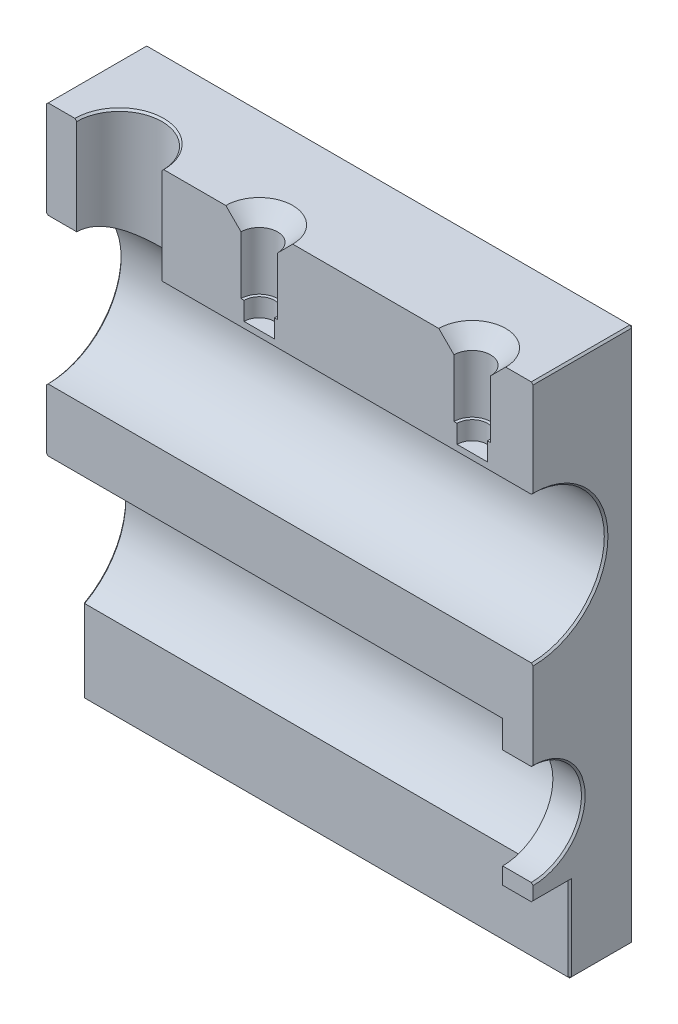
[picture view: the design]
ISO-10303-21;
HEADER;
FILE_DESCRIPTION(('STEP AP214'),'2;1');
FILE_NAME('part.step','',(''),(''),'','','');
FILE_SCHEMA(('AUTOMOTIVE_DESIGN { 1 0 10303 214 1 1 1 1 }'));
ENDSEC;
DATA;
#1=APPLICATION_CONTEXT('core data for automotive mechanical design processes');
#2=APPLICATION_PROTOCOL_DEFINITION('international standard','automotive_design',2000,#1);
#3=PRODUCT_CONTEXT('',#1,'mechanical');
#4=PRODUCT('Part','Part','',(#3));
#5=PRODUCT_RELATED_PRODUCT_CATEGORY('part','',(#4));
#6=PRODUCT_DEFINITION_FORMATION('','',#4);
#7=PRODUCT_DEFINITION_CONTEXT('part definition',#1,'design');
#8=PRODUCT_DEFINITION('design','',#6,#7);
#9=PRODUCT_DEFINITION_SHAPE('','',#8);
#10=(LENGTH_UNIT() NAMED_UNIT(*) SI_UNIT(.MILLI.,.METRE.));
#11=(NAMED_UNIT(*) PLANE_ANGLE_UNIT() SI_UNIT($,.RADIAN.));
#12=(NAMED_UNIT(*) SI_UNIT($,.STERADIAN.) SOLID_ANGLE_UNIT());
#13=UNCERTAINTY_MEASURE_WITH_UNIT(LENGTH_MEASURE(1.E-05),#10,'distance_accuracy_value','');
#14=(GEOMETRIC_REPRESENTATION_CONTEXT(3) GLOBAL_UNCERTAINTY_ASSIGNED_CONTEXT((#13)) GLOBAL_UNIT_ASSIGNED_CONTEXT((#10,
#11,#12)) REPRESENTATION_CONTEXT('',''));
#15=CARTESIAN_POINT('',(0.,0.,0.));
#16=DIRECTION('',(0.,0.,1.));
#17=DIRECTION('',(1.,0.,0.));
#18=AXIS2_PLACEMENT_3D('',#15,#16,#17);
#19=CARTESIAN_POINT('',(-40.,44.,35.));
#20=DIRECTION('',(1.,0.,0.));
#21=DIRECTION('',(0.,0.,-1.));
#22=AXIS2_PLACEMENT_3D('',#19,#20,#21);
#23=PLANE('',#22);
#24=DIRECTION('',(0.,-1.,0.));
#25=VECTOR('',#24,1.);
#26=CARTESIAN_POINT('',(-40.,63.9994038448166,16.5));
#27=LINE('',#26,#25);
#28=CARTESIAN_POINT('',(-40.,43.7,16.5));
#29=VERTEX_POINT('',#28);
#30=CARTESIAN_POINT('',(-40.,28.3,16.5));
#31=VERTEX_POINT('',#30);
#32=EDGE_CURVE('E275',#29,#31,#27,.T.);
#33=ORIENTED_EDGE('',*,*,#32,.F.);
#34=DIRECTION('',(0.,0.,-1.));
#35=VECTOR('',#34,1.);
#36=CARTESIAN_POINT('',(-40.,43.7,0.));
#37=LINE('',#36,#35);
#38=CARTESIAN_POINT('',(-40.,43.7,0.300000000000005));
#39=VERTEX_POINT('',#38);
#40=EDGE_CURVE('E287',#29,#39,#37,.T.);
#41=ORIENTED_EDGE('',*,*,#40,.T.);
#42=DIRECTION('',(0.,-1.,0.));
#43=VECTOR('',#42,1.);
#44=CARTESIAN_POINT('',(-40.,-44.,0.300000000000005));
#45=LINE('',#44,#43);
#46=CARTESIAN_POINT('',(-40.,-43.7,0.300000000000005));
#47=VERTEX_POINT('',#46);
#48=EDGE_CURVE('E299',#39,#47,#45,.T.);
#49=ORIENTED_EDGE('',*,*,#48,.T.);
#50=DIRECTION('',(0.,0.,1.));
#51=VECTOR('',#50,1.);
#52=CARTESIAN_POINT('',(-40.,-43.7,10.5));
#53=LINE('',#52,#51);
#54=CARTESIAN_POINT('',(-40.,-43.7,10.2));
#55=VERTEX_POINT('',#54);
#56=EDGE_CURVE('E302',#47,#55,#53,.T.);
#57=ORIENTED_EDGE('',*,*,#56,.T.);
#58=DIRECTION('',(0.,1.,0.));
#59=VECTOR('',#58,1.);
#60=CARTESIAN_POINT('',(-40.,-30.25,10.2));
#61=LINE('',#60,#59);
#62=CARTESIAN_POINT('',(-40.,-30.4285825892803,10.2));
#63=VERTEX_POINT('',#62);
#64=EDGE_CURVE('E310',#55,#63,#61,.T.);
#65=ORIENTED_EDGE('',*,*,#64,.T.);
#66=CARTESIAN_POINT('',(-40.,-19.,16.5));
#67=DIRECTION('',(1.,0.,0.));
#68=DIRECTION('',(0.,0.,-1.));
#69=AXIS2_PLACEMENT_3D('',#66,#67,#68);
#70=CIRCLE('',#69,13.05);
#71=CARTESIAN_POINT('',(-40.,-5.94999999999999,16.5));
#72=VERTEX_POINT('',#71);
#73=EDGE_CURVE('E312',#63,#72,#70,.T.);
#74=ORIENTED_EDGE('',*,*,#73,.T.);
#75=CARTESIAN_POINT('',(-40.,3.69999999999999,16.5));
#76=VERTEX_POINT('',#75);
#77=EDGE_CURVE('E293',#76,#72,#27,.T.);
#78=ORIENTED_EDGE('',*,*,#77,.F.);
#79=CARTESIAN_POINT('',(-40.,16.,16.5));
#80=DIRECTION('',(1.,0.,0.));
#81=DIRECTION('',(0.,0.,-1.));
#82=AXIS2_PLACEMENT_3D('',#79,#80,#81);
#83=CIRCLE('',#82,12.3);
#84=EDGE_CURVE('E291',#76,#31,#83,.T.);
#85=ORIENTED_EDGE('',*,*,#84,.T.);
#86=EDGE_LOOP('',(#33,#41,#49,#57,#65,#74,#78,#85));
#87=FACE_BOUND('',#86,.T.);
#88=ADVANCED_FACE('F34',(#87),#23,.F.);
#89=CARTESIAN_POINT('',(35.,-19.,16.5));
#90=DIRECTION('',(-1.,0.,0.));
#91=DIRECTION('',(0.,0.,1.));
#92=AXIS2_PLACEMENT_3D('',#89,#90,#91);
#93=CYLINDRICAL_SURFACE('',#92,12.75);
#94=DIRECTION('',(-1.,0.,0.));
#95=VECTOR('',#94,1.);
#96=CARTESIAN_POINT('',(35.,-6.25,16.5));
#97=LINE('',#96,#95);
#98=CARTESIAN_POINT('',(-39.7,-6.25,16.5));
#99=VERTEX_POINT('',#98);
#100=CARTESIAN_POINT('',(35.,-6.25,16.5));
#101=VERTEX_POINT('',#100);
#102=EDGE_CURVE('E463',#99,#101,#97,.F.);
#103=ORIENTED_EDGE('',*,*,#102,.F.);
#104=CARTESIAN_POINT('',(-39.7,-19.,16.5));
#105=DIRECTION('',(1.,0.,0.));
#106=DIRECTION('',(0.,0.,-1.));
#107=AXIS2_PLACEMENT_3D('',#104,#105,#106);
#108=CIRCLE('',#107,12.75);
#109=CARTESIAN_POINT('',(-39.7,-30.25,10.5));
#110=VERTEX_POINT('',#109);
#111=EDGE_CURVE('E316',#99,#110,#108,.F.);
#112=ORIENTED_EDGE('',*,*,#111,.T.);
#113=DIRECTION('',(-1.,0.,0.));
#114=VECTOR('',#113,1.);
#115=CARTESIAN_POINT('',(35.,-30.25,10.5));
#116=LINE('',#115,#114);
#117=CARTESIAN_POINT('',(35.,-30.25,10.5));
#118=VERTEX_POINT('',#117);
#119=EDGE_CURVE('E733',#110,#118,#116,.F.);
#120=ORIENTED_EDGE('',*,*,#119,.T.);
#121=CARTESIAN_POINT('',(35.,-19.,16.5));
#122=DIRECTION('',(-1.,0.,0.));
#123=DIRECTION('',(0.,0.,1.));
#124=AXIS2_PLACEMENT_3D('',#121,#122,#123);
#125=CIRCLE('',#124,12.75);
#126=EDGE_CURVE('E723',#101,#118,#125,.T.);
#127=ORIENTED_EDGE('',*,*,#126,.F.);
#128=EDGE_LOOP('',(#103,#112,#120,#127));
#129=FACE_BOUND('',#128,.T.);
#130=ADVANCED_FACE('F645',(#129),#93,.F.);
#131=CARTESIAN_POINT('',(-105.,-30.,22.5));
#132=DIRECTION('',(0.,-1.,0.));
#133=DIRECTION('',(0.,0.,-1.));
#134=AXIS2_PLACEMENT_3D('',#131,#132,#133);
#135=PLANE('',#134);
#136=DIRECTION('',(0.,0.,1.));
#137=VECTOR('',#136,1.);
#138=CARTESIAN_POINT('',(39.7,-30.,22.5));
#139=LINE('',#138,#137);
#140=CARTESIAN_POINT('',(39.7,-30.,10.5));
#141=VERTEX_POINT('',#140);
#142=CARTESIAN_POINT('',(39.7,-30.,16.5));
#143=VERTEX_POINT('',#142);
#144=EDGE_CURVE('E368',#141,#143,#139,.T.);
#145=ORIENTED_EDGE('',*,*,#144,.T.);
#146=DIRECTION('',(-1.,0.,0.));
#147=VECTOR('',#146,1.);
#148=CARTESIAN_POINT('',(-105.,-30.,16.5));
#149=LINE('',#148,#147);
#150=CARTESIAN_POINT('',(35.,-30.,16.5));
#151=VERTEX_POINT('',#150);
#152=EDGE_CURVE('E473',#143,#151,#149,.T.);
#153=ORIENTED_EDGE('',*,*,#152,.T.);
#154=DIRECTION('',(0.,0.,-1.));
#155=VECTOR('',#154,1.);
#156=CARTESIAN_POINT('',(35.,-30.,22.5));
#157=LINE('',#156,#155);
#158=CARTESIAN_POINT('',(35.,-30.,10.5));
#159=VERTEX_POINT('',#158);
#160=EDGE_CURVE('E725',#151,#159,#157,.T.);
#161=ORIENTED_EDGE('',*,*,#160,.T.);
#162=DIRECTION('',(1.,0.,0.));
#163=VECTOR('',#162,1.);
#164=CARTESIAN_POINT('',(-105.,-30.,10.5));
#165=LINE('',#164,#163);
#166=EDGE_CURVE('E727',#159,#141,#165,.T.);
#167=ORIENTED_EDGE('',*,*,#166,.T.);
#168=EDGE_LOOP('',(#145,#153,#161,#167));
#169=FACE_BOUND('',#168,.T.);
#170=ADVANCED_FACE('F636',(#169),#135,.T.);
#171=CARTESIAN_POINT('',(40.,-44.,35.));
#172=DIRECTION('',(-1.,0.,0.));
#173=DIRECTION('',(0.,-1.,0.));
#174=AXIS2_PLACEMENT_3D('',#171,#172,#173);
#175=PLANE('',#174);
#176=DIRECTION('',(0.,-1.,0.));
#177=VECTOR('',#176,1.);
#178=CARTESIAN_POINT('',(40.,63.9994038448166,16.5));
#179=LINE('',#178,#177);
#180=CARTESIAN_POINT('',(40.,-27.55,16.5));
#181=VERTEX_POINT('',#180);
#182=CARTESIAN_POINT('',(40.,-29.7,16.5));
#183=VERTEX_POINT('',#182);
#184=EDGE_CURVE('E49',#181,#183,#179,.T.);
#185=ORIENTED_EDGE('',*,*,#184,.T.);
#186=DIRECTION('',(0.,0.,-1.));
#187=VECTOR('',#186,1.);
#188=CARTESIAN_POINT('',(40.,-29.7,10.5));
#189=LINE('',#188,#187);
#190=CARTESIAN_POINT('',(40.,-29.7,10.2));
#191=VERTEX_POINT('',#190);
#192=EDGE_CURVE('E360',#183,#191,#189,.T.);
#193=ORIENTED_EDGE('',*,*,#192,.T.);
#194=DIRECTION('',(0.,-1.,0.));
#195=VECTOR('',#194,1.);
#196=CARTESIAN_POINT('',(40.,-44.,10.2));
#197=LINE('',#196,#195);
#198=CARTESIAN_POINT('',(40.,-43.7,10.2));
#199=VERTEX_POINT('',#198);
#200=EDGE_CURVE('E358',#191,#199,#197,.T.);
#201=ORIENTED_EDGE('',*,*,#200,.T.);
#202=DIRECTION('',(0.,0.,-1.));
#203=VECTOR('',#202,1.);
#204=CARTESIAN_POINT('',(40.,-43.7,0.));
#205=LINE('',#204,#203);
#206=CARTESIAN_POINT('',(40.,-43.7,0.300000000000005));
#207=VERTEX_POINT('',#206);
#208=EDGE_CURVE('E356',#199,#207,#205,.T.);
#209=ORIENTED_EDGE('',*,*,#208,.T.);
#210=DIRECTION('',(0.,1.,0.));
#211=VECTOR('',#210,1.);
#212=CARTESIAN_POINT('',(40.,44.,0.300000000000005));
#213=LINE('',#212,#211);
#214=CARTESIAN_POINT('',(40.,43.7,0.300000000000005));
#215=VERTEX_POINT('',#214);
#216=EDGE_CURVE('E354',#207,#215,#213,.T.);
#217=ORIENTED_EDGE('',*,*,#216,.T.);
#218=DIRECTION('',(0.,0.,1.));
#219=VECTOR('',#218,1.);
#220=CARTESIAN_POINT('',(40.,43.7,35.));
#221=LINE('',#220,#219);
#222=CARTESIAN_POINT('',(40.,43.7,16.5));
#223=VERTEX_POINT('',#222);
#224=EDGE_CURVE('E351',#215,#223,#221,.T.);
#225=ORIENTED_EDGE('',*,*,#224,.T.);
#226=CARTESIAN_POINT('',(40.,28.3,16.5));
#227=VERTEX_POINT('',#226);
#228=EDGE_CURVE('E659',#223,#227,#179,.T.);
#229=ORIENTED_EDGE('',*,*,#228,.T.);
#230=CARTESIAN_POINT('',(40.,16.,16.5));
#231=DIRECTION('',(-1.,0.,0.));
#232=DIRECTION('',(0.,-1.,0.));
#233=AXIS2_PLACEMENT_3D('',#230,#231,#232);
#234=CIRCLE('',#233,12.3);
#235=CARTESIAN_POINT('',(40.,3.69999999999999,16.5));
#236=VERTEX_POINT('',#235);
#237=EDGE_CURVE('E362',#227,#236,#234,.T.);
#238=ORIENTED_EDGE('',*,*,#237,.T.);
#239=CARTESIAN_POINT('',(40.,-10.45,16.5));
#240=VERTEX_POINT('',#239);
#241=EDGE_CURVE('E57',#236,#240,#179,.T.);
#242=ORIENTED_EDGE('',*,*,#241,.T.);
#243=CARTESIAN_POINT('',(40.,-19.,16.5));
#244=DIRECTION('',(-1.,0.,0.));
#245=DIRECTION('',(0.,-1.,0.));
#246=AXIS2_PLACEMENT_3D('',#243,#244,#245);
#247=CIRCLE('',#246,8.55000000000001);
#248=EDGE_CURVE('E365',#240,#181,#247,.T.);
#249=ORIENTED_EDGE('',*,*,#248,.T.);
#250=EDGE_LOOP('',(#185,#193,#201,#209,#217,#225,#229,#238,#242,#249));
#251=FACE_BOUND('',#250,.T.);
#252=ADVANCED_FACE('F647',(#251),#175,.F.);
#253=CARTESIAN_POINT('',(-40.,44.,35.));
#254=DIRECTION('',(0.,1.,0.));
#255=DIRECTION('',(-1.,0.,0.));
#256=AXIS2_PLACEMENT_3D('',#253,#254,#255);
#257=PLANE('',#256);
#258=DIRECTION('',(0.,0.,1.));
#259=VECTOR('',#258,1.);
#260=CARTESIAN_POINT('',(-39.7,44.,35.));
#261=LINE('',#260,#259);
#262=CARTESIAN_POINT('',(-39.7,44.,0.300000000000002));
#263=VERTEX_POINT('',#262);
#264=CARTESIAN_POINT('',(-39.7,44.,16.5));
#265=VERTEX_POINT('',#264);
#266=EDGE_CURVE('E346',#263,#265,#261,.T.);
#267=ORIENTED_EDGE('',*,*,#266,.T.);
#268=DIRECTION('',(1.,0.,0.));
#269=VECTOR('',#268,1.);
#270=CARTESIAN_POINT('',(-40.,44.,16.5));
#271=LINE('',#270,#269);
#272=CARTESIAN_POINT('',(-35.3,44.,16.5));
#273=VERTEX_POINT('',#272);
#274=EDGE_CURVE('E278',#265,#273,#271,.T.);
#275=ORIENTED_EDGE('',*,*,#274,.T.);
#276=CARTESIAN_POINT('',(-28.,44.,16.5));
#277=DIRECTION('',(0.,1.,0.));
#278=DIRECTION('',(-1.,0.,0.));
#279=AXIS2_PLACEMENT_3D('',#276,#277,#278);
#280=CIRCLE('',#279,7.3);
#281=CARTESIAN_POINT('',(-20.7,44.,16.5));
#282=VERTEX_POINT('',#281);
#283=EDGE_CURVE('E348',#273,#282,#280,.F.);
#284=ORIENTED_EDGE('',*,*,#283,.T.);
#285=CARTESIAN_POINT('',(-10.5,44.,16.5));
#286=VERTEX_POINT('',#285);
#287=EDGE_CURVE('E393',#282,#286,#271,.T.);
#288=ORIENTED_EDGE('',*,*,#287,.T.);
#289=CARTESIAN_POINT('',(-5.,44.,16.5));
#290=DIRECTION('',(0.,1.,0.));
#291=DIRECTION('',(-1.,0.,0.));
#292=AXIS2_PLACEMENT_3D('',#289,#290,#291);
#293=CIRCLE('',#292,5.50000000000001);
#294=CARTESIAN_POINT('',(0.500000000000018,44.,16.5));
#295=VERTEX_POINT('',#294);
#296=EDGE_CURVE('E746',#286,#295,#293,.F.);
#297=ORIENTED_EDGE('',*,*,#296,.T.);
#298=CARTESIAN_POINT('',(24.5,44.,16.5));
#299=VERTEX_POINT('',#298);
#300=EDGE_CURVE('E422',#295,#299,#271,.T.);
#301=ORIENTED_EDGE('',*,*,#300,.T.);
#302=CARTESIAN_POINT('',(30.,44.,16.5));
#303=DIRECTION('',(0.,1.,0.));
#304=DIRECTION('',(-1.,0.,0.));
#305=AXIS2_PLACEMENT_3D('',#302,#303,#304);
#306=CIRCLE('',#305,5.50000000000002);
#307=CARTESIAN_POINT('',(35.5,44.,16.5));
#308=VERTEX_POINT('',#307);
#309=EDGE_CURVE('E752',#299,#308,#306,.F.);
#310=ORIENTED_EDGE('',*,*,#309,.T.);
#311=CARTESIAN_POINT('',(39.7,44.,16.5));
#312=VERTEX_POINT('',#311);
#313=EDGE_CURVE('E444',#308,#312,#271,.T.);
#314=ORIENTED_EDGE('',*,*,#313,.T.);
#315=DIRECTION('',(0.,0.,-1.));
#316=VECTOR('',#315,1.);
#317=CARTESIAN_POINT('',(39.7,44.,0.));
#318=LINE('',#317,#316);
#319=CARTESIAN_POINT('',(39.7,44.,0.300000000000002));
#320=VERTEX_POINT('',#319);
#321=EDGE_CURVE('E342',#312,#320,#318,.T.);
#322=ORIENTED_EDGE('',*,*,#321,.T.);
#323=DIRECTION('',(-1.,0.,0.));
#324=VECTOR('',#323,1.);
#325=CARTESIAN_POINT('',(-40.,44.,0.300000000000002));
#326=LINE('',#325,#324);
#327=EDGE_CURVE('E344',#320,#263,#326,.T.);
#328=ORIENTED_EDGE('',*,*,#327,.T.);
#329=EDGE_LOOP('',(#267,#275,#284,#288,#297,#301,#310,#314,#322,#328));
#330=FACE_BOUND('',#329,.T.);
#331=ADVANCED_FACE('F634',(#330),#257,.T.);
#332=CARTESIAN_POINT('',(105.,16.,16.5));
#333=DIRECTION('',(-1.,0.,0.));
#334=DIRECTION('',(0.,0.,1.));
#335=AXIS2_PLACEMENT_3D('',#332,#333,#334);
#336=CYLINDRICAL_SURFACE('',#335,12.);
#337=DIRECTION('',(-1.,0.,0.));
#338=VECTOR('',#337,1.);
#339=CARTESIAN_POINT('',(105.,28.,16.5));
#340=LINE('',#339,#338);
#341=CARTESIAN_POINT('',(-39.7,28.,16.5));
#342=VERTEX_POINT('',#341);
#343=CARTESIAN_POINT('',(-35.,28.,16.5));
#344=VERTEX_POINT('',#343);
#345=EDGE_CURVE('E395',#342,#344,#340,.F.);
#346=ORIENTED_EDGE('',*,*,#345,.F.);
#347=CARTESIAN_POINT('',(-39.7,16.,16.5));
#348=DIRECTION('',(1.,0.,0.));
#349=DIRECTION('',(0.,0.,-1.));
#350=AXIS2_PLACEMENT_3D('',#347,#348,#349);
#351=CIRCLE('',#350,12.);
#352=CARTESIAN_POINT('',(-39.7,4.,16.5));
#353=VERTEX_POINT('',#352);
#354=EDGE_CURVE('E300',#342,#353,#351,.F.);
#355=ORIENTED_EDGE('',*,*,#354,.T.);
#356=DIRECTION('',(-1.,0.,0.));
#357=VECTOR('',#356,1.);
#358=CARTESIAN_POINT('',(105.,4.,16.5));
#359=LINE('',#358,#357);
#360=CARTESIAN_POINT('',(39.7,4.,16.5));
#361=VERTEX_POINT('',#360);
#362=EDGE_CURVE('E450',#361,#353,#359,.T.);
#363=ORIENTED_EDGE('',*,*,#362,.F.);
#364=CARTESIAN_POINT('',(39.7,16.,16.5));
#365=DIRECTION('',(-1.,0.,0.));
#366=DIRECTION('',(0.,0.,1.));
#367=AXIS2_PLACEMENT_3D('',#364,#365,#366);
#368=CIRCLE('',#367,12.);
#369=CARTESIAN_POINT('',(39.7,28.,16.5));
#370=VERTEX_POINT('',#369);
#371=EDGE_CURVE('E305',#361,#370,#368,.F.);
#372=ORIENTED_EDGE('',*,*,#371,.T.);
#373=CARTESIAN_POINT('',(-21.,28.,16.5));
#374=VERTEX_POINT('',#373);
#375=EDGE_CURVE('E391',#374,#370,#340,.F.);
#376=ORIENTED_EDGE('',*,*,#375,.F.);
#377=CARTESIAN_POINT('',(-35.,28.,16.5));
#378=CARTESIAN_POINT('',(-34.9999987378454,27.9999988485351,16.6799242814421));
#379=CARTESIAN_POINT('',(-34.9930513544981,27.9959425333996,16.8599175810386));
#380=CARTESIAN_POINT('',(-34.965347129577,27.979813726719,17.2185590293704));
#381=CARTESIAN_POINT('',(-34.9445808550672,27.9677357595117,17.397206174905));
#382=CARTESIAN_POINT('',(-34.8894535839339,27.9358311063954,17.7520940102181));
#383=CARTESIAN_POINT('',(-34.8550630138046,27.9159875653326,17.9283285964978));
#384=CARTESIAN_POINT('',(-34.7731150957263,27.8690337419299,18.2767862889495));
#385=CARTESIAN_POINT('',(-34.7255520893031,27.8419203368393,18.449007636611));
#386=CARTESIAN_POINT('',(-34.6181125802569,27.7812332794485,18.7873368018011));
#387=CARTESIAN_POINT('',(-34.5583041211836,27.7476953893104,18.9534726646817));
#388=CARTESIAN_POINT('',(-34.4268387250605,27.6748137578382,19.2796970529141));
#389=CARTESIAN_POINT('',(-34.3551772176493,27.6354677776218,19.4397832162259));
#390=CARTESIAN_POINT('',(-34.1234941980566,27.5100054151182,19.9094672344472));
#391=CARTESIAN_POINT('',(-33.9466262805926,27.4163786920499,20.2089503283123));
#392=CARTESIAN_POINT('',(-33.538685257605,27.2090985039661,20.7965672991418));
#393=CARTESIAN_POINT('',(-33.3045675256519,27.0944753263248,21.0822174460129));
#394=CARTESIAN_POINT('',(-32.7952979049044,26.8601889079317,21.6127667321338));
#395=CARTESIAN_POINT('',(-32.5200951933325,26.7405195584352,21.8576145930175));
#396=CARTESIAN_POINT('',(-32.0633107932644,26.558790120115,22.2036501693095));
#397=CARTESIAN_POINT('',(-31.8941627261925,26.4946617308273,22.3204771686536));
#398=CARTESIAN_POINT('',(-31.5451446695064,26.370220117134,22.5394008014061));
#399=CARTESIAN_POINT('',(-31.3652730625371,26.3099074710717,22.6414952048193));
#400=CARTESIAN_POINT('',(-30.9959052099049,26.1953257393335,22.8298884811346));
#401=CARTESIAN_POINT('',(-30.806421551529,26.1410490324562,22.9162073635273));
#402=CARTESIAN_POINT('',(-30.4186545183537,26.0406610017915,23.0721943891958));
#403=CARTESIAN_POINT('',(-30.220374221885,25.9945468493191,23.141868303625));
#404=CARTESIAN_POINT('',(-29.8628196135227,25.922039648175,23.2495419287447));
#405=CARTESIAN_POINT('',(-29.7050462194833,25.8935497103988,23.2911410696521));
#406=CARTESIAN_POINT('',(-29.3859307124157,25.8435761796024,23.3633769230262));
#407=CARTESIAN_POINT('',(-29.2245893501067,25.8220911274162,23.3940159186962));
#408=CARTESIAN_POINT('',(-28.8994699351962,25.7868769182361,23.4439164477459));
#409=CARTESIAN_POINT('',(-28.7356943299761,25.7731404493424,23.4631887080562));
#410=CARTESIAN_POINT('',(-28.40670027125,25.7538937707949,23.4901239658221));
#411=CARTESIAN_POINT('',(-28.2414817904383,25.7483837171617,23.4977867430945));
#412=CARTESIAN_POINT('',(-27.9105866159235,25.7457981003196,23.5013873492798));
#413=CARTESIAN_POINT('',(-27.7449096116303,25.7487359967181,23.4973064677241));
#414=CARTESIAN_POINT('',(-27.414623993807,25.7629626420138,23.4774427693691));
#415=CARTESIAN_POINT('',(-27.2500153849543,25.7742514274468,23.461659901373));
#416=CARTESIAN_POINT('',(-26.9229899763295,25.8047656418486,23.4186171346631));
#417=CARTESIAN_POINT('',(-26.7605741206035,25.8239943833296,23.3913524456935));
#418=CARTESIAN_POINT('',(-26.4389929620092,25.8697209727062,23.3257017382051));
#419=CARTESIAN_POINT('',(-26.2798290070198,25.8962217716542,23.287311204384));
#420=CARTESIAN_POINT('',(-25.9669297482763,25.9553982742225,23.20020827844));
#421=CARTESIAN_POINT('',(-25.8131615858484,25.9880237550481,23.151579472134));
#422=CARTESIAN_POINT('',(-25.510410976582,26.0586461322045,23.0442920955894));
#423=CARTESIAN_POINT('',(-25.3614301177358,26.0966447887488,22.9856302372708));
#424=CARTESIAN_POINT('',(-24.9225783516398,26.2172134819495,22.7953246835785));
#425=CARTESIAN_POINT('',(-24.6406438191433,26.3063871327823,22.6493174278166));
#426=CARTESIAN_POINT('',(-24.0564857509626,26.5101947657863,22.295173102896));
#427=CARTESIAN_POINT('',(-23.7586926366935,26.6265962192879,22.0807404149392));
#428=CARTESIAN_POINT('',(-23.3402045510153,26.8026719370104,21.7268306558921));
#429=CARTESIAN_POINT('',(-23.2053174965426,26.8616545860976,21.6033783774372));
#430=CARTESIAN_POINT('',(-22.9453933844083,26.9788695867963,21.3460690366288));
#431=CARTESIAN_POINT('',(-22.8203580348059,27.0371018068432,21.212210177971));
#432=CARTESIAN_POINT('',(-22.5658626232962,27.1586667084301,20.9173138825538));
#433=CARTESIAN_POINT('',(-22.4377884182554,27.2217322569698,20.7549672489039));
#434=CARTESIAN_POINT('',(-22.195887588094,27.3435800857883,20.4185680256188));
#435=CARTESIAN_POINT('',(-22.0820552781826,27.4023640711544,20.2445201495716));
#436=CARTESIAN_POINT('',(-21.8696422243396,27.514040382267,19.8855855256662));
#437=CARTESIAN_POINT('',(-21.7710587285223,27.5669337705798,19.7007007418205));
#438=CARTESIAN_POINT('',(-21.5902466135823,27.6652982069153,19.3212090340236));
#439=CARTESIAN_POINT('',(-21.5080159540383,27.7107701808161,19.1266033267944));
#440=CARTESIAN_POINT('',(-21.3659479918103,27.7901405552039,18.7424190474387));
#441=CARTESIAN_POINT('',(-21.3049795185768,27.8246102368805,18.5533771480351));
#442=CARTESIAN_POINT('',(-21.19908556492,27.884887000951,18.1694901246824));
#443=CARTESIAN_POINT('',(-21.1541595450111,27.9106943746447,17.9746451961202));
#444=CARTESIAN_POINT('',(-21.0810785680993,27.9528483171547,17.5810015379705));
#445=CARTESIAN_POINT('',(-21.0529086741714,27.9692033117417,17.3822064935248));
#446=CARTESIAN_POINT('',(-21.0137528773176,27.991971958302,16.9823739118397));
#447=CARTESIAN_POINT('',(-21.0027648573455,27.9983868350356,16.781336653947));
#448=CARTESIAN_POINT('',(-20.9984475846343,28.0009058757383,16.4046741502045));
#449=CARTESIAN_POINT('',(-21.0030457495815,27.9982202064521,16.2290764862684));
#450=CARTESIAN_POINT('',(-21.0253944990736,27.9852007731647,15.8790052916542));
#451=CARTESIAN_POINT('',(-21.0431447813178,27.9748671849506,15.7045317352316));
#452=CARTESIAN_POINT('',(-21.0915660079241,27.946801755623,15.3580072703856));
#453=CARTESIAN_POINT('',(-21.1222362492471,27.9290703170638,15.1859562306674));
#454=CARTESIAN_POINT('',(-21.1961171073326,27.8866273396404,14.8454506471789));
#455=CARTESIAN_POINT('',(-21.2393280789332,27.8619156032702,14.6769962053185));
#456=CARTESIAN_POINT('',(-21.3370112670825,27.8065162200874,14.3474104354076));
#457=CARTESIAN_POINT('',(-21.3912916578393,27.7759308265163,14.1862049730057));
#458=CARTESIAN_POINT('',(-21.510979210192,27.7091816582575,13.8691523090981));
#459=CARTESIAN_POINT('',(-21.5763899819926,27.673016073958,13.7133068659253));
#460=CARTESIAN_POINT('',(-21.7884493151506,27.5572161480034,13.2550384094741));
#461=CARTESIAN_POINT('',(-21.9509951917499,27.4702377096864,12.9616490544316));
#462=CARTESIAN_POINT('',(-22.3326222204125,27.2734064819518,12.37495536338));
#463=CARTESIAN_POINT('',(-22.555831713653,27.1621140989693,12.0848514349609));
#464=CARTESIAN_POINT('',(-23.0432916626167,26.9326417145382,11.5438217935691));
#465=CARTESIAN_POINT('',(-23.3075898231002,26.8144538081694,11.2929423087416));
#466=CARTESIAN_POINT('',(-23.7481456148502,26.6328528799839,10.9355367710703));
#467=CARTESIAN_POINT('',(-23.912000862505,26.5682105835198,10.8140507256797));
#468=CARTESIAN_POINT('',(-24.2505815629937,26.4419087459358,10.5853076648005));
#469=CARTESIAN_POINT('',(-24.4253097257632,26.3802499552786,10.4780542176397));
#470=CARTESIAN_POINT('',(-24.7846784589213,26.2620430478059,10.2787542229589));
#471=CARTESIAN_POINT('',(-24.9693106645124,26.2054907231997,10.1866951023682));
#472=CARTESIAN_POINT('',(-25.3476313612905,26.0996108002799,10.0186633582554));
#473=CARTESIAN_POINT('',(-25.5413132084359,26.0502780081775,9.9426791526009));
#474=CARTESIAN_POINT('',(-25.894050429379,25.9705659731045,9.82228743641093));
#475=CARTESIAN_POINT('',(-26.0515884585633,25.9383925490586,9.77460351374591));
#476=CARTESIAN_POINT('',(-26.3707267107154,25.8807857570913,9.69025070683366));
#477=CARTESIAN_POINT('',(-26.5323247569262,25.8553488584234,9.65357605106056));
#478=CARTESIAN_POINT('',(-26.8585667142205,25.8120721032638,9.59169557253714));
#479=CARTESIAN_POINT('',(-27.0232078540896,25.7942256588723,9.56647980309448));
#480=CARTESIAN_POINT('',(-27.3545581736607,25.7667467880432,9.52782507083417));
#481=CARTESIAN_POINT('',(-27.5212673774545,25.7571144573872,9.5143862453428));
#482=CARTESIAN_POINT('',(-27.855951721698,25.7464199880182,9.49947260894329));
#483=CARTESIAN_POINT('',(-28.0239290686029,25.7453811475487,9.49803032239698));
#484=CARTESIAN_POINT('',(-28.3593803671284,25.7519757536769,9.50721802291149));
#485=CARTESIAN_POINT('',(-28.5268543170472,25.7596092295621,9.51784805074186));
#486=CARTESIAN_POINT('',(-28.8600682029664,25.7832553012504,9.55101969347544));
#487=CARTESIAN_POINT('',(-29.025807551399,25.7992706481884,9.57356521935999));
#488=CARTESIAN_POINT('',(-29.3543963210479,25.8390941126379,9.63025307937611));
#489=CARTESIAN_POINT('',(-29.517244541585,25.8629053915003,9.66440011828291));
#490=CARTESIAN_POINT('',(-29.8341783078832,25.9166803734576,9.74266092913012));
#491=CARTESIAN_POINT('',(-29.9883802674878,25.946438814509,9.78644614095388));
#492=CARTESIAN_POINT('',(-30.292360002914,26.011635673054,9.88406539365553));
#493=CARTESIAN_POINT('',(-30.442136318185,26.0470759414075,9.93790270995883));
#494=CARTESIAN_POINT('',(-30.883847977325,26.1604956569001,10.1137793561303));
#495=CARTESIAN_POINT('',(-31.1683244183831,26.2456025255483,10.2502230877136));
#496=CARTESIAN_POINT('',(-31.7559866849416,26.4412152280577,10.5819384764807));
#497=CARTESIAN_POINT('',(-32.0552420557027,26.5536132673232,10.7830494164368));
#498=CARTESIAN_POINT('',(-32.4775724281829,26.72530391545,11.1163603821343));
#499=CARTESIAN_POINT('',(-32.614008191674,26.7830904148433,11.2328288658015));
#500=CARTESIAN_POINT('',(-32.877635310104,26.8984984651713,11.4759756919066));
#501=CARTESIAN_POINT('',(-33.0048251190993,26.9561199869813,11.6026557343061));
#502=CARTESIAN_POINT('',(-33.2665773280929,27.0779780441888,11.8842517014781));
#503=CARTESIAN_POINT('',(-33.399663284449,27.1420060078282,12.0406336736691));
#504=CARTESIAN_POINT('',(-33.6521414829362,27.266527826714,12.3653212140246));
#505=CARTESIAN_POINT('',(-33.771538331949,27.3270228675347,12.5336227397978));
#506=CARTESIAN_POINT('',(-33.9957745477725,27.4429058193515,12.8815010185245));
#507=CARTESIAN_POINT('',(-34.100604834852,27.4982905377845,13.0610847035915));
#508=CARTESIAN_POINT('',(-34.2945268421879,27.6023434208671,13.4304046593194));
#509=CARTESIAN_POINT('',(-34.3836209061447,27.651012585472,13.6201394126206));
#510=CARTESIAN_POINT('',(-34.5411584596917,27.7380855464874,13.9993237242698));
#511=CARTESIAN_POINT('',(-34.610378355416,27.7768655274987,14.188363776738));
#512=CARTESIAN_POINT('',(-34.732595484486,27.8458978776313,14.5731165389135));
#513=CARTESIAN_POINT('',(-34.7855957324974,27.8761518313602,14.7688280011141));
#514=CARTESIAN_POINT('',(-34.8744337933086,27.9271337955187,15.1646440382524));
#515=CARTESIAN_POINT('',(-34.9103267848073,27.9478924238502,15.3647322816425));
#516=CARTESIAN_POINT('',(-34.9645814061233,27.9793530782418,15.767937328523));
#517=CARTESIAN_POINT('',(-34.9829587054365,27.9900640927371,15.9710512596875));
#518=CARTESIAN_POINT('',(-34.9949552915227,27.9970579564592,16.2287983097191));
#519=CARTESIAN_POINT('',(-34.9968464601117,27.9981606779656,16.2830132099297));
#520=CARTESIAN_POINT('',(-34.9993690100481,27.9996318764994,16.3914833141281));
#521=CARTESIAN_POINT('',(-35.00000038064,28.0000003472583,16.445738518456));
#522=CARTESIAN_POINT('',(-35.,28.,16.5));
#523=B_SPLINE_CURVE_WITH_KNOTS('',3,(#377,#378,#379,#380,#381,#382,#383,#384,#385,#386,#387,
#388,#389,#390,#391,#392,#393,#394,#395,#396,#397,#398,#399,#400,#401,#402,#403,#404,#405,#406,
#407,#408,#409,#410,#411,#412,#413,#414,#415,#416,#417,#418,#419,#420,#421,#422,#423,#424,#425,
#426,#427,#428,#429,#430,#431,#432,#433,#434,#435,#436,#437,#438,#439,#440,#441,#442,#443,#444,
#445,#446,#447,#448,#449,#450,#451,#452,#453,#454,#455,#456,#457,#458,#459,#460,#461,#462,#463,
#464,#465,#466,#467,#468,#469,#470,#471,#472,#473,#474,#475,#476,#477,#478,#479,#480,#481,#482,
#483,#484,#485,#486,#487,#488,#489,#490,#491,#492,#493,#494,#495,#496,#497,#498,#499,#500,#501,
#502,#503,#504,#505,#506,#507,#508,#509,#510,#511,#512,#513,#514,#515,#516,#517,#518,#519,#520,
#521,#522),.UNSPECIFIED.,.T.,.F.,(4,2,2,2,2,2,2,2,2,2,2,2,2,2,2,2,2,2,2,2,2,2,2,2,2,2,2,2,2,2,2,
2,2,2,2,2,2,2,2,2,2,2,2,2,2,2,2,2,2,2,2,2,2,2,2,2,2,2,2,2,2,2,2,2,2,2,2,2,2,2,2,2,4),(0.,
0.539714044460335,1.07979688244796,1.62105852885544,2.16255304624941,2.7011165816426,
3.23988826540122,4.3159766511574,5.47177129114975,6.62900769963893,7.27436377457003,
7.91981743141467,8.56444663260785,9.20885200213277,9.70525094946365,10.2015464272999,
10.6973727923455,11.1932085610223,11.6898347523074,12.1864631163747,12.6832988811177,
13.1803365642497,13.673463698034,14.1667527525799,15.1528453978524,16.3030243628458,
16.8789854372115,17.4550461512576,18.102797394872,18.7502892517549,19.3976641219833,
20.0449581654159,20.6488864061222,21.2527943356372,21.8561631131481,22.459457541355,
22.985843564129,23.5122174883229,24.0385627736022,24.5649229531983,25.0828370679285,
25.6009194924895,26.6363484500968,27.7797710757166,28.9245312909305,29.5658181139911,
30.2072654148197,30.8481792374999,31.4886296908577,31.9912636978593,32.4936337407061,
32.9955668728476,33.497505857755,34.0008052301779,34.5041063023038,35.0075726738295,
35.5112434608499,35.999853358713,36.4886227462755,37.4656692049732,38.594099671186,
39.1590902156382,39.7241750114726,40.3686847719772,41.0129769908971,41.6576690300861,
42.3022649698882,42.9164261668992,43.5304731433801,44.1425259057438,44.7540306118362,
44.9167959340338,45.0795626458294),.UNSPECIFIED.);
#524=EDGE_CURVE('E388',#374,#344,#523,.T.);
#525=ORIENTED_EDGE('',*,*,#524,.T.);
#526=EDGE_LOOP('',(#346,#355,#363,#372,#376,#525));
#527=FACE_BOUND('',#526,.T.);
#528=ADVANCED_FACE('F628',(#527),#336,.F.);
#529=CARTESIAN_POINT('',(35.,-19.,16.5));
#530=DIRECTION('',(-1.,0.,0.));
#531=DIRECTION('',(0.,0.,1.));
#532=AXIS2_PLACEMENT_3D('',#529,#530,#531);
#533=PLANE('',#532);
#534=ORIENTED_EDGE('',*,*,#160,.F.);
#535=DIRECTION('',(0.,1.,0.));
#536=VECTOR('',#535,1.);
#537=CARTESIAN_POINT('',(35.,-19.,16.5));
#538=LINE('',#537,#536);
#539=CARTESIAN_POINT('',(35.,-27.25,16.5));
#540=VERTEX_POINT('',#539);
#541=EDGE_CURVE('E464',#151,#540,#538,.T.);
#542=ORIENTED_EDGE('',*,*,#541,.T.);
#543=CARTESIAN_POINT('',(35.,-19.,16.5));
#544=DIRECTION('',(-1.,0.,0.));
#545=DIRECTION('',(0.,0.,1.));
#546=AXIS2_PLACEMENT_3D('',#543,#544,#545);
#547=CIRCLE('',#546,8.25);
#548=CARTESIAN_POINT('',(35.,-10.75,16.5));
#549=VERTEX_POINT('',#548);
#550=EDGE_CURVE('E720',#549,#540,#547,.T.);
#551=ORIENTED_EDGE('',*,*,#550,.F.);
#552=EDGE_CURVE('E460',#549,#101,#538,.T.);
#553=ORIENTED_EDGE('',*,*,#552,.T.);
#554=ORIENTED_EDGE('',*,*,#126,.T.);
#555=DIRECTION('',(0.,-1.,0.));
#556=VECTOR('',#555,1.);
#557=CARTESIAN_POINT('',(35.,-30.,10.5));
#558=LINE('',#557,#556);
#559=EDGE_CURVE('E730',#159,#118,#558,.T.);
#560=ORIENTED_EDGE('',*,*,#559,.F.);
#561=EDGE_LOOP('',(#534,#542,#551,#553,#554,#560));
#562=FACE_BOUND('',#561,.T.);
#563=ADVANCED_FACE('F633',(#562),#533,.T.);
#564=CARTESIAN_POINT('',(40.,-19.,16.5));
#565=DIRECTION('',(-1.,0.,0.));
#566=DIRECTION('',(0.,0.,1.));
#567=AXIS2_PLACEMENT_3D('',#564,#565,#566);
#568=CYLINDRICAL_SURFACE('',#567,8.25);
#569=DIRECTION('',(-1.,0.,0.));
#570=VECTOR('',#569,1.);
#571=CARTESIAN_POINT('',(40.,-10.75,16.5));
#572=LINE('',#571,#570);
#573=CARTESIAN_POINT('',(39.7,-10.75,16.5));
#574=VERTEX_POINT('',#573);
#575=EDGE_CURVE('E458',#549,#574,#572,.F.);
#576=ORIENTED_EDGE('',*,*,#575,.F.);
#577=ORIENTED_EDGE('',*,*,#550,.T.);
#578=DIRECTION('',(-1.,0.,0.));
#579=VECTOR('',#578,1.);
#580=CARTESIAN_POINT('',(40.,-27.25,16.5));
#581=LINE('',#580,#579);
#582=CARTESIAN_POINT('',(39.7,-27.25,16.5));
#583=VERTEX_POINT('',#582);
#584=EDGE_CURVE('E471',#583,#540,#581,.T.);
#585=ORIENTED_EDGE('',*,*,#584,.F.);
#586=CARTESIAN_POINT('',(39.7,-19.,16.5));
#587=DIRECTION('',(-1.,0.,0.));
#588=DIRECTION('',(0.,0.,1.));
#589=AXIS2_PLACEMENT_3D('',#586,#587,#588);
#590=CIRCLE('',#589,8.25);
#591=EDGE_CURVE('E371',#583,#574,#590,.F.);
#592=ORIENTED_EDGE('',*,*,#591,.T.);
#593=EDGE_LOOP('',(#576,#577,#585,#592));
#594=FACE_BOUND('',#593,.T.);
#595=ADVANCED_FACE('F613',(#594),#568,.F.);
#596=CARTESIAN_POINT('',(-28.,19.,16.5));
#597=DIRECTION('',(0.,1.,0.));
#598=DIRECTION('',(-1.,0.,0.));
#599=AXIS2_PLACEMENT_3D('',#596,#597,#598);
#600=CYLINDRICAL_SURFACE('',#599,7.);
#601=DIRECTION('',(0.,1.,0.));
#602=VECTOR('',#601,1.);
#603=CARTESIAN_POINT('',(-21.,19.,16.5));
#604=LINE('',#603,#602);
#605=CARTESIAN_POINT('',(-21.,43.7,16.5));
#606=VERTEX_POINT('',#605);
#607=EDGE_CURVE('E387',#606,#374,#604,.F.);
#608=ORIENTED_EDGE('',*,*,#607,.F.);
#609=CARTESIAN_POINT('',(-28.,43.7,16.5));
#610=DIRECTION('',(0.,1.,0.));
#611=DIRECTION('',(0.,0.,1.));
#612=AXIS2_PLACEMENT_3D('',#609,#610,#611);
#613=CIRCLE('',#612,7.);
#614=CARTESIAN_POINT('',(-35.,43.7,16.5));
#615=VERTEX_POINT('',#614);
#616=EDGE_CURVE('E374',#606,#615,#613,.T.);
#617=ORIENTED_EDGE('',*,*,#616,.T.);
#618=DIRECTION('',(0.,1.,0.));
#619=VECTOR('',#618,1.);
#620=CARTESIAN_POINT('',(-35.,19.,16.5));
#621=LINE('',#620,#619);
#622=EDGE_CURVE('E292',#344,#615,#621,.T.);
#623=ORIENTED_EDGE('',*,*,#622,.F.);
#624=ORIENTED_EDGE('',*,*,#524,.F.);
#625=EDGE_LOOP('',(#608,#617,#623,#624));
#626=FACE_BOUND('',#625,.T.);
#627=ADVANCED_FACE('F384',(#626),#600,.F.);
#628=CARTESIAN_POINT('',(30.,32.,16.5));
#629=DIRECTION('',(0.,1.,0.));
#630=DIRECTION('',(-1.,0.,0.));
#631=AXIS2_PLACEMENT_3D('',#628,#629,#630);
#632=PLANE('',#631);
#633=CARTESIAN_POINT('',(30.,32.,16.5));
#634=DIRECTION('',(0.,1.,0.));
#635=DIRECTION('',(-1.,0.,0.));
#636=AXIS2_PLACEMENT_3D('',#633,#634,#635);
#637=CIRCLE('',#636,3.);
#638=CARTESIAN_POINT('',(33.,32.,16.5));
#639=VERTEX_POINT('',#638);
#640=CARTESIAN_POINT('',(27.,32.,16.5));
#641=VERTEX_POINT('',#640);
#642=EDGE_CURVE('E706',#639,#641,#637,.T.);
#643=ORIENTED_EDGE('',*,*,#642,.T.);
#644=DIRECTION('',(1.,0.,0.));
#645=VECTOR('',#644,1.);
#646=CARTESIAN_POINT('',(30.,32.,16.5));
#647=LINE('',#646,#645);
#648=CARTESIAN_POINT('',(27.5,32.,16.5));
#649=VERTEX_POINT('',#648);
#650=EDGE_CURVE('E428',#641,#649,#647,.T.);
#651=ORIENTED_EDGE('',*,*,#650,.T.);
#652=CARTESIAN_POINT('',(30.,32.,16.5));
#653=DIRECTION('',(0.,1.,0.));
#654=DIRECTION('',(-1.,0.,0.));
#655=AXIS2_PLACEMENT_3D('',#652,#653,#654);
#656=CIRCLE('',#655,2.50000000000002);
#657=CARTESIAN_POINT('',(32.5,32.,16.5));
#658=VERTEX_POINT('',#657);
#659=EDGE_CURVE('E626',#649,#658,#656,.F.);
#660=ORIENTED_EDGE('',*,*,#659,.T.);
#661=EDGE_CURVE('E432',#658,#639,#647,.T.);
#662=ORIENTED_EDGE('',*,*,#661,.T.);
#663=EDGE_LOOP('',(#643,#651,#660,#662));
#664=FACE_BOUND('',#663,.T.);
#665=ADVANCED_FACE('F589',(#664),#632,.T.);
#666=CARTESIAN_POINT('',(30.,32.,16.5));
#667=DIRECTION('',(0.,1.,0.));
#668=DIRECTION('',(-1.,0.,0.));
#669=AXIS2_PLACEMENT_3D('',#666,#667,#668);
#670=CYLINDRICAL_SURFACE('',#669,3.);
#671=DIRECTION('',(0.,1.,0.));
#672=VECTOR('',#671,1.);
#673=CARTESIAN_POINT('',(33.,32.,16.5));
#674=LINE('',#673,#672);
#675=CARTESIAN_POINT('',(33.,41.4999999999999,16.5));
#676=VERTEX_POINT('',#675);
#677=EDGE_CURVE('E439',#676,#639,#674,.F.);
#678=ORIENTED_EDGE('',*,*,#677,.F.);
#679=CARTESIAN_POINT('',(30.,41.4999999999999,16.5));
#680=DIRECTION('',(0.,1.,0.));
#681=DIRECTION('',(0.,0.,1.));
#682=AXIS2_PLACEMENT_3D('',#679,#680,#681);
#683=CIRCLE('',#682,3.);
#684=CARTESIAN_POINT('',(27.,41.4999999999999,16.5));
#685=VERTEX_POINT('',#684);
#686=EDGE_CURVE('E742',#676,#685,#683,.T.);
#687=ORIENTED_EDGE('',*,*,#686,.T.);
#688=DIRECTION('',(0.,1.,0.));
#689=VECTOR('',#688,1.);
#690=CARTESIAN_POINT('',(27.,32.,16.5));
#691=LINE('',#690,#689);
#692=EDGE_CURVE('E426',#641,#685,#691,.T.);
#693=ORIENTED_EDGE('',*,*,#692,.F.);
#694=ORIENTED_EDGE('',*,*,#642,.F.);
#695=EDGE_LOOP('',(#678,#687,#693,#694));
#696=FACE_BOUND('',#695,.T.);
#697=ADVANCED_FACE('F592',(#696),#670,.F.);
#698=CARTESIAN_POINT('',(30.,29.,16.5));
#699=DIRECTION('',(0.,1.,0.));
#700=DIRECTION('',(-1.,0.,0.));
#701=AXIS2_PLACEMENT_3D('',#698,#699,#700);
#702=PLANE('',#701);
#703=CARTESIAN_POINT('',(30.,29.,16.5));
#704=DIRECTION('',(0.,1.,0.));
#705=DIRECTION('',(-1.,0.,0.));
#706=AXIS2_PLACEMENT_3D('',#703,#704,#705);
#707=CIRCLE('',#706,2.50000000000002);
#708=CARTESIAN_POINT('',(32.5,29.,16.5));
#709=VERTEX_POINT('',#708);
#710=CARTESIAN_POINT('',(27.5,29.,16.5));
#711=VERTEX_POINT('',#710);
#712=EDGE_CURVE('E623',#709,#711,#707,.T.);
#713=ORIENTED_EDGE('',*,*,#712,.T.);
#714=DIRECTION('',(1.,0.,0.));
#715=VECTOR('',#714,1.);
#716=CARTESIAN_POINT('',(30.,29.,16.5));
#717=LINE('',#716,#715);
#718=EDGE_CURVE('E434',#711,#709,#717,.T.);
#719=ORIENTED_EDGE('',*,*,#718,.T.);
#720=EDGE_LOOP('',(#713,#719));
#721=FACE_BOUND('',#720,.T.);
#722=ADVANCED_FACE('F596',(#721),#702,.T.);
#723=CARTESIAN_POINT('',(30.,29.,16.5));
#724=DIRECTION('',(0.,1.,0.));
#725=DIRECTION('',(-1.,0.,0.));
#726=AXIS2_PLACEMENT_3D('',#723,#724,#725);
#727=CYLINDRICAL_SURFACE('',#726,2.50000000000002);
#728=DIRECTION('',(0.,1.,0.));
#729=VECTOR('',#728,1.);
#730=CARTESIAN_POINT('',(32.5,29.,16.5));
#731=LINE('',#730,#729);
#732=EDGE_CURVE('E437',#658,#709,#731,.F.);
#733=ORIENTED_EDGE('',*,*,#732,.F.);
#734=ORIENTED_EDGE('',*,*,#659,.F.);
#735=DIRECTION('',(0.,1.,0.));
#736=VECTOR('',#735,1.);
#737=CARTESIAN_POINT('',(27.5,29.,16.5));
#738=LINE('',#737,#736);
#739=EDGE_CURVE('E431',#711,#649,#738,.T.);
#740=ORIENTED_EDGE('',*,*,#739,.F.);
#741=ORIENTED_EDGE('',*,*,#712,.F.);
#742=EDGE_LOOP('',(#733,#734,#740,#741));
#743=FACE_BOUND('',#742,.T.);
#744=ADVANCED_FACE('F583',(#743),#727,.F.);
#745=CARTESIAN_POINT('',(-5.,32.,16.5));
#746=DIRECTION('',(0.,1.,0.));
#747=DIRECTION('',(-1.,0.,0.));
#748=AXIS2_PLACEMENT_3D('',#745,#746,#747);
#749=PLANE('',#748);
#750=CARTESIAN_POINT('',(-5.,32.,16.5));
#751=DIRECTION('',(0.,1.,0.));
#752=DIRECTION('',(-1.,0.,0.));
#753=AXIS2_PLACEMENT_3D('',#750,#751,#752);
#754=CIRCLE('',#753,3.);
#755=CARTESIAN_POINT('',(-2.,32.,16.5));
#756=VERTEX_POINT('',#755);
#757=CARTESIAN_POINT('',(-8.,32.,16.5));
#758=VERTEX_POINT('',#757);
#759=EDGE_CURVE('E702',#756,#758,#754,.T.);
#760=ORIENTED_EDGE('',*,*,#759,.T.);
#761=DIRECTION('',(1.,0.,0.));
#762=VECTOR('',#761,1.);
#763=CARTESIAN_POINT('',(-5.,32.,16.5));
#764=LINE('',#763,#762);
#765=CARTESIAN_POINT('',(-7.50000000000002,32.,16.5));
#766=VERTEX_POINT('',#765);
#767=EDGE_CURVE('E406',#758,#766,#764,.T.);
#768=ORIENTED_EDGE('',*,*,#767,.T.);
#769=CARTESIAN_POINT('',(-5.,32.,16.5));
#770=DIRECTION('',(0.,1.,0.));
#771=DIRECTION('',(-1.,0.,0.));
#772=AXIS2_PLACEMENT_3D('',#769,#770,#771);
#773=CIRCLE('',#772,2.50000000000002);
#774=CARTESIAN_POINT('',(-2.49999999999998,32.,16.5));
#775=VERTEX_POINT('',#774);
#776=EDGE_CURVE('E705',#766,#775,#773,.F.);
#777=ORIENTED_EDGE('',*,*,#776,.T.);
#778=EDGE_CURVE('E410',#775,#756,#764,.T.);
#779=ORIENTED_EDGE('',*,*,#778,.T.);
#780=EDGE_LOOP('',(#760,#768,#777,#779));
#781=FACE_BOUND('',#780,.T.);
#782=ADVANCED_FACE('F579',(#781),#749,.T.);
#783=CARTESIAN_POINT('',(-5.,32.,16.5));
#784=DIRECTION('',(0.,1.,0.));
#785=DIRECTION('',(-1.,0.,0.));
#786=AXIS2_PLACEMENT_3D('',#783,#784,#785);
#787=CYLINDRICAL_SURFACE('',#786,3.);
#788=DIRECTION('',(0.,1.,0.));
#789=VECTOR('',#788,1.);
#790=CARTESIAN_POINT('',(-2.,32.,16.5));
#791=LINE('',#790,#789);
#792=CARTESIAN_POINT('',(-2.,41.5,16.5));
#793=VERTEX_POINT('',#792);
#794=EDGE_CURVE('E417',#793,#756,#791,.F.);
#795=ORIENTED_EDGE('',*,*,#794,.F.);
#796=CARTESIAN_POINT('',(-5.,41.5,16.5));
#797=DIRECTION('',(0.,1.,0.));
#798=DIRECTION('',(0.,0.,1.));
#799=AXIS2_PLACEMENT_3D('',#796,#797,#798);
#800=CIRCLE('',#799,3.);
#801=CARTESIAN_POINT('',(-7.99999999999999,41.5,16.5));
#802=VERTEX_POINT('',#801);
#803=EDGE_CURVE('E757',#793,#802,#800,.T.);
#804=ORIENTED_EDGE('',*,*,#803,.T.);
#805=DIRECTION('',(0.,1.,0.));
#806=VECTOR('',#805,1.);
#807=CARTESIAN_POINT('',(-8.,32.,16.5));
#808=LINE('',#807,#806);
#809=EDGE_CURVE('E404',#758,#802,#808,.T.);
#810=ORIENTED_EDGE('',*,*,#809,.F.);
#811=ORIENTED_EDGE('',*,*,#759,.F.);
#812=EDGE_LOOP('',(#795,#804,#810,#811));
#813=FACE_BOUND('',#812,.T.);
#814=ADVANCED_FACE('F582',(#813),#787,.F.);
#815=CARTESIAN_POINT('',(-5.,29.,16.5));
#816=DIRECTION('',(0.,1.,0.));
#817=DIRECTION('',(-1.,0.,0.));
#818=AXIS2_PLACEMENT_3D('',#815,#816,#817);
#819=PLANE('',#818);
#820=CARTESIAN_POINT('',(-5.,29.,16.5));
#821=DIRECTION('',(0.,1.,0.));
#822=DIRECTION('',(-1.,0.,0.));
#823=AXIS2_PLACEMENT_3D('',#820,#821,#822);
#824=CIRCLE('',#823,2.50000000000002);
#825=CARTESIAN_POINT('',(-2.49999999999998,29.,16.5));
#826=VERTEX_POINT('',#825);
#827=CARTESIAN_POINT('',(-7.50000000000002,29.,16.5));
#828=VERTEX_POINT('',#827);
#829=EDGE_CURVE('E709',#826,#828,#824,.T.);
#830=ORIENTED_EDGE('',*,*,#829,.T.);
#831=DIRECTION('',(1.,0.,0.));
#832=VECTOR('',#831,1.);
#833=CARTESIAN_POINT('',(-5.,29.,16.5));
#834=LINE('',#833,#832);
#835=EDGE_CURVE('E412',#828,#826,#834,.T.);
#836=ORIENTED_EDGE('',*,*,#835,.T.);
#837=EDGE_LOOP('',(#830,#836));
#838=FACE_BOUND('',#837,.T.);
#839=ADVANCED_FACE('F587',(#838),#819,.T.);
#840=CARTESIAN_POINT('',(-5.,29.,16.5));
#841=DIRECTION('',(0.,1.,0.));
#842=DIRECTION('',(-1.,0.,0.));
#843=AXIS2_PLACEMENT_3D('',#840,#841,#842);
#844=CYLINDRICAL_SURFACE('',#843,2.50000000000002);
#845=DIRECTION('',(0.,1.,0.));
#846=VECTOR('',#845,1.);
#847=CARTESIAN_POINT('',(-2.49999999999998,29.,16.5));
#848=LINE('',#847,#846);
#849=EDGE_CURVE('E415',#775,#826,#848,.F.);
#850=ORIENTED_EDGE('',*,*,#849,.F.);
#851=ORIENTED_EDGE('',*,*,#776,.F.);
#852=DIRECTION('',(0.,1.,0.));
#853=VECTOR('',#852,1.);
#854=CARTESIAN_POINT('',(-7.50000000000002,29.,16.5));
#855=LINE('',#854,#853);
#856=EDGE_CURVE('E409',#828,#766,#855,.T.);
#857=ORIENTED_EDGE('',*,*,#856,.F.);
#858=ORIENTED_EDGE('',*,*,#829,.F.);
#859=EDGE_LOOP('',(#850,#851,#857,#858));
#860=FACE_BOUND('',#859,.T.);
#861=ADVANCED_FACE('F577',(#860),#844,.F.);
#862=CARTESIAN_POINT('',(30.,41.4999999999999,16.5));
#863=DIRECTION('',(0.,1.,0.));
#864=DIRECTION('',(0.,0.,1.));
#865=AXIS2_PLACEMENT_3D('',#862,#863,#864);
#866=CONICAL_SURFACE('',#865,3.,0.785398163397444);
#867=ORIENTED_EDGE('',*,*,#686,.F.);
#868=DIRECTION('',(0.707106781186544,0.707106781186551,0.));
#869=VECTOR('',#868,1.);
#870=CARTESIAN_POINT('',(30.,38.4999999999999,16.5));
#871=LINE('',#870,#869);
#872=EDGE_CURVE('E441',#676,#308,#871,.T.);
#873=ORIENTED_EDGE('',*,*,#872,.T.);
#874=ORIENTED_EDGE('',*,*,#309,.F.);
#875=DIRECTION('',(0.707106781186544,-0.707106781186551,0.));
#876=VECTOR('',#875,1.);
#877=CARTESIAN_POINT('',(30.,38.4999999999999,16.5));
#878=LINE('',#877,#876);
#879=EDGE_CURVE('E423',#299,#685,#878,.T.);
#880=ORIENTED_EDGE('',*,*,#879,.T.);
#881=EDGE_LOOP('',(#867,#873,#874,#880));
#882=FACE_BOUND('',#881,.T.);
#883=ADVANCED_FACE('F573',(#882),#866,.F.);
#884=CARTESIAN_POINT('',(-5.,41.5,16.5));
#885=DIRECTION('',(0.,1.,0.));
#886=DIRECTION('',(0.,0.,1.));
#887=AXIS2_PLACEMENT_3D('',#884,#885,#886);
#888=CONICAL_SURFACE('',#887,3.,0.785398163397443);
#889=ORIENTED_EDGE('',*,*,#803,.F.);
#890=DIRECTION('',(0.707106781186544,0.707106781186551,0.));
#891=VECTOR('',#890,1.);
#892=CARTESIAN_POINT('',(-5.,38.4999999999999,16.5));
#893=LINE('',#892,#891);
#894=EDGE_CURVE('E419',#793,#295,#893,.T.);
#895=ORIENTED_EDGE('',*,*,#894,.T.);
#896=ORIENTED_EDGE('',*,*,#296,.F.);
#897=DIRECTION('',(0.707106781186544,-0.707106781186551,0.));
#898=VECTOR('',#897,1.);
#899=CARTESIAN_POINT('',(-5.,38.4999999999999,16.5));
#900=LINE('',#899,#898);
#901=EDGE_CURVE('E401',#286,#802,#900,.T.);
#902=ORIENTED_EDGE('',*,*,#901,.T.);
#903=EDGE_LOOP('',(#889,#895,#896,#902));
#904=FACE_BOUND('',#903,.T.);
#905=ADVANCED_FACE('F569',(#904),#888,.F.);
#906=CARTESIAN_POINT('',(-39.7,16.,16.5));
#907=DIRECTION('',(-1.,0.,0.));
#908=DIRECTION('',(0.,0.,1.));
#909=AXIS2_PLACEMENT_3D('',#906,#907,#908);
#910=CONICAL_SURFACE('',#909,12.,0.785398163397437);
#911=ORIENTED_EDGE('',*,*,#354,.F.);
#912=DIRECTION('',(-0.707106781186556,0.707106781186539,0.));
#913=VECTOR('',#912,1.);
#914=CARTESIAN_POINT('',(-27.6999999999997,16.,16.5));
#915=LINE('',#914,#913);
#916=EDGE_CURVE('E283',#342,#31,#915,.T.);
#917=ORIENTED_EDGE('',*,*,#916,.T.);
#918=ORIENTED_EDGE('',*,*,#84,.F.);
#919=DIRECTION('',(0.707106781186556,0.707106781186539,0.));
#920=VECTOR('',#919,1.);
#921=CARTESIAN_POINT('',(-27.6999999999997,16.,16.5));
#922=LINE('',#921,#920);
#923=EDGE_CURVE('E452',#76,#353,#922,.T.);
#924=ORIENTED_EDGE('',*,*,#923,.T.);
#925=EDGE_LOOP('',(#911,#917,#918,#924));
#926=FACE_BOUND('',#925,.T.);
#927=ADVANCED_FACE('F553',(#926),#910,.F.);
#928=CARTESIAN_POINT('',(39.7,44.,35.));
#929=DIRECTION('',(0.707106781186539,0.707106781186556,0.));
#930=DIRECTION('',(-0.707106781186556,0.707106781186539,0.));
#931=AXIS2_PLACEMENT_3D('',#928,#929,#930);
#932=PLANE('',#931);
#933=ORIENTED_EDGE('',*,*,#321,.F.);
#934=DIRECTION('',(0.707106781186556,-0.707106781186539,0.));
#935=VECTOR('',#934,1.);
#936=CARTESIAN_POINT('',(39.7,44.,16.5));
#937=LINE('',#936,#935);
#938=EDGE_CURVE('E445',#312,#223,#937,.T.);
#939=ORIENTED_EDGE('',*,*,#938,.T.);
#940=ORIENTED_EDGE('',*,*,#224,.F.);
#941=DIRECTION('',(0.707106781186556,-0.707106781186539,0.));
#942=VECTOR('',#941,1.);
#943=CARTESIAN_POINT('',(40.,43.7,0.300000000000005));
#944=LINE('',#943,#942);
#945=EDGE_CURVE('E693',#215,#320,#944,.F.);
#946=ORIENTED_EDGE('',*,*,#945,.T.);
#947=EDGE_LOOP('',(#933,#939,#940,#946));
#948=FACE_BOUND('',#947,.T.);
#949=ADVANCED_FACE('F549',(#948),#932,.T.);
#950=CARTESIAN_POINT('',(40.,-29.7,35.));
#951=DIRECTION('',(0.707106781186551,-0.707106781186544,0.));
#952=DIRECTION('',(0.707106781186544,0.707106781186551,0.));
#953=AXIS2_PLACEMENT_3D('',#950,#951,#952);
#954=PLANE('',#953);
#955=ORIENTED_EDGE('',*,*,#192,.F.);
#956=DIRECTION('',(-0.707106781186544,-0.707106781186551,0.));
#957=VECTOR('',#956,1.);
#958=CARTESIAN_POINT('',(40.,-29.7,16.5));
#959=LINE('',#958,#957);
#960=EDGE_CURVE('E476',#183,#143,#959,.T.);
#961=ORIENTED_EDGE('',*,*,#960,.T.);
#962=ORIENTED_EDGE('',*,*,#144,.F.);
#963=DIRECTION('',(0.577350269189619,0.577350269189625,-0.577350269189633));
#964=VECTOR('',#963,1.);
#965=CARTESIAN_POINT('',(35.2333333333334,-34.4666666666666,14.9666666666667));
#966=LINE('',#965,#964);
#967=EDGE_CURVE('E662',#191,#141,#966,.F.);
#968=ORIENTED_EDGE('',*,*,#967,.F.);
#969=EDGE_LOOP('',(#955,#961,#962,#968));
#970=FACE_BOUND('',#969,.T.);
#971=ADVANCED_FACE('F522',(#970),#954,.T.);
#972=CARTESIAN_POINT('',(-40.,43.7,35.));
#973=DIRECTION('',(-0.707106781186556,0.707106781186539,0.));
#974=DIRECTION('',(-0.707106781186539,-0.707106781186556,0.));
#975=AXIS2_PLACEMENT_3D('',#972,#973,#974);
#976=PLANE('',#975);
#977=ORIENTED_EDGE('',*,*,#40,.F.);
#978=DIRECTION('',(0.707106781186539,0.707106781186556,0.));
#979=VECTOR('',#978,1.);
#980=CARTESIAN_POINT('',(-40.,43.7,16.5));
#981=LINE('',#980,#979);
#982=EDGE_CURVE('E272',#29,#265,#981,.T.);
#983=ORIENTED_EDGE('',*,*,#982,.T.);
#984=ORIENTED_EDGE('',*,*,#266,.F.);
#985=DIRECTION('',(0.707106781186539,0.707106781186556,0.));
#986=VECTOR('',#985,1.);
#987=CARTESIAN_POINT('',(-39.85,43.85,0.300000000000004));
#988=LINE('',#987,#986);
#989=EDGE_CURVE('E297',#263,#39,#988,.F.);
#990=ORIENTED_EDGE('',*,*,#989,.T.);
#991=EDGE_LOOP('',(#977,#983,#984,#990));
#992=FACE_BOUND('',#991,.T.);
#993=ADVANCED_FACE('F295',(#992),#976,.T.);
#994=CARTESIAN_POINT('',(-39.7,-19.,16.5));
#995=DIRECTION('',(-1.,0.,0.));
#996=DIRECTION('',(0.,0.,1.));
#997=AXIS2_PLACEMENT_3D('',#994,#995,#996);
#998=CONICAL_SURFACE('',#997,12.75,0.785398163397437);
#999=ORIENTED_EDGE('',*,*,#111,.F.);
#1000=DIRECTION('',(-0.707106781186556,0.707106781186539,0.));
#1001=VECTOR('',#1000,1.);
#1002=CARTESIAN_POINT('',(-26.9499999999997,-19.,16.5));
#1003=LINE('',#1002,#1001);
#1004=EDGE_CURVE('E466',#99,#72,#1003,.T.);
#1005=ORIENTED_EDGE('',*,*,#1004,.T.);
#1006=ORIENTED_EDGE('',*,*,#73,.F.);
#1007=CARTESIAN_POINT('',(-39.7,-30.25,10.5));
#1008=CARTESIAN_POINT('',(-39.7499407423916,-30.2799628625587,10.4500592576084));
#1009=CARTESIAN_POINT('',(-39.7999111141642,-30.3098261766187,10.4000888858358));
#1010=CARTESIAN_POINT('',(-39.899911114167,-30.3693537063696,10.300088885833));
#1011=CARTESIAN_POINT('',(-39.9499407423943,-30.3990179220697,10.2500592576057));
#1012=CARTESIAN_POINT('',(-40.,-30.4285825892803,10.2));
#1013=B_SPLINE_CURVE_WITH_KNOTS('',3,(#1007,#1008,#1009,#1010,#1011,#1012),.UNSPECIFIED.,.F.,
.F.,(4,2,4),(0.,0.230158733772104,0.460317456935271),.UNSPECIFIED.);
#1014=EDGE_CURVE('E479',#63,#110,#1013,.F.);
#1015=ORIENTED_EDGE('',*,*,#1014,.T.);
#1016=EDGE_LOOP('',(#999,#1005,#1006,#1015));
#1017=FACE_BOUND('',#1016,.T.);
#1018=ADVANCED_FACE('F493',(#1017),#998,.F.);
#1019=CARTESIAN_POINT('',(40.,-19.,16.5));
#1020=DIRECTION('',(1.,0.,0.));
#1021=DIRECTION('',(0.,0.,-1.));
#1022=AXIS2_PLACEMENT_3D('',#1019,#1020,#1021);
#1023=CONICAL_SURFACE('',#1022,8.55000000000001,0.785398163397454);
#1024=ORIENTED_EDGE('',*,*,#591,.F.);
#1025=DIRECTION('',(0.707106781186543,-0.707106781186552,0.));
#1026=VECTOR('',#1025,1.);
#1027=CARTESIAN_POINT('',(31.4500000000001,-19.,16.5));
#1028=LINE('',#1027,#1026);
#1029=EDGE_CURVE('E469',#583,#181,#1028,.T.);
#1030=ORIENTED_EDGE('',*,*,#1029,.T.);
#1031=ORIENTED_EDGE('',*,*,#248,.F.);
#1032=DIRECTION('',(-0.707106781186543,-0.707106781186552,0.));
#1033=VECTOR('',#1032,1.);
#1034=CARTESIAN_POINT('',(31.4500000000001,-19.,16.5));
#1035=LINE('',#1034,#1033);
#1036=EDGE_CURVE('E455',#240,#574,#1035,.T.);
#1037=ORIENTED_EDGE('',*,*,#1036,.T.);
#1038=EDGE_LOOP('',(#1024,#1030,#1031,#1037));
#1039=FACE_BOUND('',#1038,.T.);
#1040=ADVANCED_FACE('F497',(#1039),#1023,.F.);
#1041=CARTESIAN_POINT('',(40.,16.,16.5));
#1042=DIRECTION('',(1.,0.,0.));
#1043=DIRECTION('',(0.,0.,-1.));
#1044=AXIS2_PLACEMENT_3D('',#1041,#1042,#1043);
#1045=CONICAL_SURFACE('',#1044,12.3,0.785398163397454);
#1046=ORIENTED_EDGE('',*,*,#371,.F.);
#1047=DIRECTION('',(0.707106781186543,-0.707106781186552,0.));
#1048=VECTOR('',#1047,1.);
#1049=CARTESIAN_POINT('',(27.7000000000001,16.,16.5));
#1050=LINE('',#1049,#1048);
#1051=EDGE_CURVE('E448',#361,#236,#1050,.T.);
#1052=ORIENTED_EDGE('',*,*,#1051,.T.);
#1053=ORIENTED_EDGE('',*,*,#237,.F.);
#1054=DIRECTION('',(-0.707106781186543,-0.707106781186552,0.));
#1055=VECTOR('',#1054,1.);
#1056=CARTESIAN_POINT('',(27.7000000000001,16.,16.5));
#1057=LINE('',#1056,#1055);
#1058=EDGE_CURVE('E398',#227,#370,#1057,.T.);
#1059=ORIENTED_EDGE('',*,*,#1058,.T.);
#1060=EDGE_LOOP('',(#1046,#1052,#1053,#1059));
#1061=FACE_BOUND('',#1060,.T.);
#1062=ADVANCED_FACE('F764',(#1061),#1045,.F.);
#1063=CARTESIAN_POINT('',(-28.,43.7,16.5));
#1064=DIRECTION('',(0.,1.,0.));
#1065=DIRECTION('',(0.,0.,1.));
#1066=AXIS2_PLACEMENT_3D('',#1063,#1064,#1065);
#1067=CONICAL_SURFACE('',#1066,7.,0.785398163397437);
#1068=ORIENTED_EDGE('',*,*,#616,.F.);
#1069=DIRECTION('',(0.707106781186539,0.707106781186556,0.));
#1070=VECTOR('',#1069,1.);
#1071=CARTESIAN_POINT('',(-28.,36.6999999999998,16.5));
#1072=LINE('',#1071,#1070);
#1073=EDGE_CURVE('E11',#606,#282,#1072,.T.);
#1074=ORIENTED_EDGE('',*,*,#1073,.T.);
#1075=ORIENTED_EDGE('',*,*,#283,.F.);
#1076=DIRECTION('',(0.707106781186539,-0.707106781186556,0.));
#1077=VECTOR('',#1076,1.);
#1078=CARTESIAN_POINT('',(-28.,36.6999999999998,16.5));
#1079=LINE('',#1078,#1077);
#1080=EDGE_CURVE('E42',#273,#615,#1079,.T.);
#1081=ORIENTED_EDGE('',*,*,#1080,.T.);
#1082=EDGE_LOOP('',(#1068,#1074,#1075,#1081));
#1083=FACE_BOUND('',#1082,.T.);
#1084=ADVANCED_FACE('F380',(#1083),#1067,.F.);
#1085=CARTESIAN_POINT('',(40.,-44.,35.));
#1086=DIRECTION('',(0.,-1.,0.));
#1087=DIRECTION('',(0.,0.,-1.));
#1088=AXIS2_PLACEMENT_3D('',#1085,#1086,#1087);
#1089=PLANE('',#1088);
#1090=DIRECTION('',(0.,0.,-1.));
#1091=VECTOR('',#1090,1.);
#1092=CARTESIAN_POINT('',(-39.7,-44.,0.));
#1093=LINE('',#1092,#1091);
#1094=CARTESIAN_POINT('',(-39.7,-44.,10.2));
#1095=VERTEX_POINT('',#1094);
#1096=CARTESIAN_POINT('',(-39.7,-44.,0.300000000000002));
#1097=VERTEX_POINT('',#1096);
#1098=EDGE_CURVE('E328',#1095,#1097,#1093,.T.);
#1099=ORIENTED_EDGE('',*,*,#1098,.T.);
#1100=DIRECTION('',(1.,0.,0.));
#1101=VECTOR('',#1100,1.);
#1102=CARTESIAN_POINT('',(40.,-44.,0.300000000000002));
#1103=LINE('',#1102,#1101);
#1104=CARTESIAN_POINT('',(39.7,-44.,0.300000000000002));
#1105=VERTEX_POINT('',#1104);
#1106=EDGE_CURVE('E331',#1097,#1105,#1103,.T.);
#1107=ORIENTED_EDGE('',*,*,#1106,.T.);
#1108=DIRECTION('',(0.,0.,1.));
#1109=VECTOR('',#1108,1.);
#1110=CARTESIAN_POINT('',(39.7,-44.,10.5));
#1111=LINE('',#1110,#1109);
#1112=CARTESIAN_POINT('',(39.7,-44.,10.2));
#1113=VERTEX_POINT('',#1112);
#1114=EDGE_CURVE('E326',#1105,#1113,#1111,.T.);
#1115=ORIENTED_EDGE('',*,*,#1114,.T.);
#1116=DIRECTION('',(-1.,0.,0.));
#1117=VECTOR('',#1116,1.);
#1118=CARTESIAN_POINT('',(40.,-44.,10.2));
#1119=LINE('',#1118,#1117);
#1120=EDGE_CURVE('E324',#1113,#1095,#1119,.T.);
#1121=ORIENTED_EDGE('',*,*,#1120,.T.);
#1122=EDGE_LOOP('',(#1099,#1107,#1115,#1121));
#1123=FACE_BOUND('',#1122,.T.);
#1124=CARTESIAN_POINT('',(-10.,-44.,3.49999999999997));
#1125=DIRECTION('',(0.,-1.,0.));
#1126=DIRECTION('',(0.,0.,-1.));
#1127=AXIS2_PLACEMENT_3D('',#1124,#1125,#1126);
#1128=CIRCLE('',#1127,3.);
#1129=CARTESIAN_POINT('',(-10.,-44.,0.499999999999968));
#1130=VERTEX_POINT('',#1129);
#1131=EDGE_CURVE('E622',#1130,#1130,#1128,.T.);
#1132=ORIENTED_EDGE('',*,*,#1131,.F.);
#1133=EDGE_LOOP('',(#1132));
#1134=FACE_BOUND('',#1133,.T.);
#1135=ADVANCED_FACE('F36',(#1123,#1134),#1089,.T.);
#1136=CARTESIAN_POINT('',(-40.,-44.,0.));
#1137=DIRECTION('',(0.,0.,-1.));
#1138=DIRECTION('',(-1.,0.,0.));
#1139=AXIS2_PLACEMENT_3D('',#1136,#1137,#1138);
#1140=PLANE('',#1139);
#1141=DIRECTION('',(-1.,0.,0.));
#1142=VECTOR('',#1141,1.);
#1143=CARTESIAN_POINT('',(-40.,-43.7,0.));
#1144=LINE('',#1143,#1142);
#1145=CARTESIAN_POINT('',(39.7,-43.7,0.));
#1146=VERTEX_POINT('',#1145);
#1147=CARTESIAN_POINT('',(-39.7,-43.7,0.));
#1148=VERTEX_POINT('',#1147);
#1149=EDGE_CURVE('E337',#1146,#1148,#1144,.T.);
#1150=ORIENTED_EDGE('',*,*,#1149,.T.);
#1151=DIRECTION('',(0.,1.,0.));
#1152=VECTOR('',#1151,1.);
#1153=CARTESIAN_POINT('',(-39.7,44.,0.));
#1154=LINE('',#1153,#1152);
#1155=CARTESIAN_POINT('',(-39.7,43.7,0.));
#1156=VERTEX_POINT('',#1155);
#1157=EDGE_CURVE('E339',#1148,#1156,#1154,.T.);
#1158=ORIENTED_EDGE('',*,*,#1157,.T.);
#1159=DIRECTION('',(1.,0.,0.));
#1160=VECTOR('',#1159,1.);
#1161=CARTESIAN_POINT('',(-40.,43.7,0.));
#1162=LINE('',#1161,#1160);
#1163=CARTESIAN_POINT('',(39.7,43.7,0.));
#1164=VERTEX_POINT('',#1163);
#1165=EDGE_CURVE('E333',#1156,#1164,#1162,.T.);
#1166=ORIENTED_EDGE('',*,*,#1165,.T.);
#1167=DIRECTION('',(0.,-1.,0.));
#1168=VECTOR('',#1167,1.);
#1169=CARTESIAN_POINT('',(39.7,-44.,0.));
#1170=LINE('',#1169,#1168);
#1171=EDGE_CURVE('E335',#1164,#1146,#1170,.T.);
#1172=ORIENTED_EDGE('',*,*,#1171,.T.);
#1173=EDGE_LOOP('',(#1150,#1158,#1166,#1172));
#1174=FACE_BOUND('',#1173,.T.);
#1175=ADVANCED_FACE('F638',(#1174),#1140,.T.);
#1176=CARTESIAN_POINT('',(-105.,-30.,10.5));
#1177=DIRECTION('',(0.,0.,1.));
#1178=DIRECTION('',(0.,-1.,0.));
#1179=AXIS2_PLACEMENT_3D('',#1176,#1177,#1178);
#1180=PLANE('',#1179);
#1181=ORIENTED_EDGE('',*,*,#119,.F.);
#1182=DIRECTION('',(0.,-1.,0.));
#1183=VECTOR('',#1182,1.);
#1184=CARTESIAN_POINT('',(-39.7,-44.,10.5));
#1185=LINE('',#1184,#1183);
#1186=CARTESIAN_POINT('',(-39.7,-43.7,10.5));
#1187=VERTEX_POINT('',#1186);
#1188=EDGE_CURVE('E322',#110,#1187,#1185,.T.);
#1189=ORIENTED_EDGE('',*,*,#1188,.T.);
#1190=DIRECTION('',(1.,0.,0.));
#1191=VECTOR('',#1190,1.);
#1192=CARTESIAN_POINT('',(-105.,-43.7,10.5));
#1193=LINE('',#1192,#1191);
#1194=CARTESIAN_POINT('',(39.7,-43.7,10.5));
#1195=VERTEX_POINT('',#1194);
#1196=EDGE_CURVE('E318',#1187,#1195,#1193,.T.);
#1197=ORIENTED_EDGE('',*,*,#1196,.T.);
#1198=DIRECTION('',(0.,1.,0.));
#1199=VECTOR('',#1198,1.);
#1200=CARTESIAN_POINT('',(39.7,-30.,10.5));
#1201=LINE('',#1200,#1199);
#1202=EDGE_CURVE('E320',#1195,#141,#1201,.T.);
#1203=ORIENTED_EDGE('',*,*,#1202,.T.);
#1204=ORIENTED_EDGE('',*,*,#166,.F.);
#1205=ORIENTED_EDGE('',*,*,#559,.T.);
#1206=EDGE_LOOP('',(#1181,#1189,#1197,#1203,#1204,#1205));
#1207=FACE_BOUND('',#1206,.T.);
#1208=ADVANCED_FACE('F641',(#1207),#1180,.T.);
#1209=CARTESIAN_POINT('',(-10.,-34.,3.49999999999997));
#1210=DIRECTION('',(0.,-1.,0.));
#1211=DIRECTION('',(0.,0.,-1.));
#1212=AXIS2_PLACEMENT_3D('',#1209,#1210,#1211);
#1213=CYLINDRICAL_SURFACE('',#1212,3.);
#1214=CARTESIAN_POINT('',(-10.,-34.,3.49999999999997));
#1215=DIRECTION('',(0.,-1.,0.));
#1216=DIRECTION('',(0.,0.,-1.));
#1217=AXIS2_PLACEMENT_3D('',#1214,#1215,#1216);
#1218=CIRCLE('',#1217,3.);
#1219=CARTESIAN_POINT('',(-10.,-34.,0.499999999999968));
#1220=VERTEX_POINT('',#1219);
#1221=EDGE_CURVE('E716',#1220,#1220,#1218,.T.);
#1222=ORIENTED_EDGE('',*,*,#1221,.F.);
#1223=EDGE_LOOP('',(#1222));
#1224=FACE_BOUND('',#1223,.T.);
#1225=ORIENTED_EDGE('',*,*,#1131,.T.);
#1226=EDGE_LOOP('',(#1225));
#1227=FACE_BOUND('',#1226,.T.);
#1228=ADVANCED_FACE('F844',(#1224,#1227),#1213,.F.);
#1229=CARTESIAN_POINT('',(-10.,-34.,3.49999999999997));
#1230=DIRECTION('',(0.,-1.,0.));
#1231=DIRECTION('',(0.,0.,-1.));
#1232=AXIS2_PLACEMENT_3D('',#1229,#1230,#1231);
#1233=PLANE('',#1232);
#1234=CARTESIAN_POINT('',(-10.,-34.,3.49999999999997));
#1235=DIRECTION('',(0.,-1.,0.));
#1236=DIRECTION('',(0.,0.,-1.));
#1237=AXIS2_PLACEMENT_3D('',#1234,#1235,#1236);
#1238=CIRCLE('',#1237,2.25);
#1239=CARTESIAN_POINT('',(-10.,-34.,1.24999999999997));
#1240=VERTEX_POINT('',#1239);
#1241=EDGE_CURVE('E719',#1240,#1240,#1238,.T.);
#1242=ORIENTED_EDGE('',*,*,#1241,.F.);
#1243=EDGE_LOOP('',(#1242));
#1244=FACE_BOUND('',#1243,.T.);
#1245=ORIENTED_EDGE('',*,*,#1221,.T.);
#1246=EDGE_LOOP('',(#1245));
#1247=FACE_BOUND('',#1246,.T.);
#1248=ADVANCED_FACE('F846',(#1244,#1247),#1233,.T.);
#1249=CARTESIAN_POINT('',(-10.,-30.,3.49999999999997));
#1250=DIRECTION('',(0.,1.,0.));
#1251=DIRECTION('',(0.,0.,1.));
#1252=AXIS2_PLACEMENT_3D('',#1249,#1250,#1251);
#1253=PLANE('',#1252);
#1254=CARTESIAN_POINT('',(-10.,-30.,3.49999999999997));
#1255=DIRECTION('',(0.,1.,0.));
#1256=DIRECTION('',(0.,0.,1.));
#1257=AXIS2_PLACEMENT_3D('',#1254,#1255,#1256);
#1258=CIRCLE('',#1257,0.249999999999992);
#1259=CARTESIAN_POINT('',(-10.,-30.,3.24999999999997));
#1260=VERTEX_POINT('',#1259);
#1261=EDGE_CURVE('E624',#1260,#1260,#1258,.F.);
#1262=ORIENTED_EDGE('',*,*,#1261,.T.);
#1263=EDGE_LOOP('',(#1262));
#1264=FACE_BOUND('',#1263,.T.);
#1265=ADVANCED_FACE('F849',(#1264),#1253,.F.);
#1266=CARTESIAN_POINT('',(-10.,-30.,3.49999999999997));
#1267=DIRECTION('',(0.,-1.,0.));
#1268=DIRECTION('',(0.,0.,-1.));
#1269=AXIS2_PLACEMENT_3D('',#1266,#1267,#1268);
#1270=CYLINDRICAL_SURFACE('',#1269,2.25);
#1271=CARTESIAN_POINT('',(-10.,-31.1547005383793,3.49999999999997));
#1272=DIRECTION('',(0.,1.,0.));
#1273=DIRECTION('',(0.,0.,1.));
#1274=AXIS2_PLACEMENT_3D('',#1271,#1272,#1273);
#1275=CIRCLE('',#1274,2.25);
#1276=CARTESIAN_POINT('',(-10.,-31.1547005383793,1.24999999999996));
#1277=VERTEX_POINT('',#1276);
#1278=EDGE_CURVE('E736',#1277,#1277,#1275,.T.);
#1279=ORIENTED_EDGE('',*,*,#1278,.T.);
#1280=EDGE_LOOP('',(#1279));
#1281=FACE_BOUND('',#1280,.T.);
#1282=ORIENTED_EDGE('',*,*,#1241,.T.);
#1283=EDGE_LOOP('',(#1282));
#1284=FACE_BOUND('',#1283,.T.);
#1285=ADVANCED_FACE('F858',(#1281,#1284),#1270,.F.);
#1286=CARTESIAN_POINT('',(-10.,-31.1547005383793,3.49999999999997));
#1287=DIRECTION('',(0.,-1.,0.));
#1288=DIRECTION('',(0.,0.,-1.));
#1289=AXIS2_PLACEMENT_3D('',#1286,#1287,#1288);
#1290=CONICAL_SURFACE('',#1289,2.25,1.04719755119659);
#1291=CARTESIAN_POINT('',(-10.,-30.,3.24999999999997));
#1292=CARTESIAN_POINT('',(-10.,-30.0120281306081,3.22916666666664));
#1293=CARTESIAN_POINT('',(-10.,-30.0240562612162,3.20833333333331));
#1294=CARTESIAN_POINT('',(-10.,-30.0481125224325,3.16666666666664));
#1295=CARTESIAN_POINT('',(-10.,-30.0601406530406,3.14583333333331));
#1296=CARTESIAN_POINT('',(-10.,-30.0841969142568,3.10416666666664));
#1297=CARTESIAN_POINT('',(-10.,-30.0962250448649,3.08333333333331));
#1298=CARTESIAN_POINT('',(-10.,-30.1202813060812,3.04166666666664));
#1299=CARTESIAN_POINT('',(-10.,-30.1323094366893,3.02083333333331));
#1300=CARTESIAN_POINT('',(-10.,-30.1563656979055,2.97916666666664));
#1301=CARTESIAN_POINT('',(-10.,-30.1683938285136,2.95833333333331));
#1302=CARTESIAN_POINT('',(-10.,-30.1924500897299,2.91666666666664));
#1303=CARTESIAN_POINT('',(-10.,-30.204478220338,2.8958333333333));
#1304=CARTESIAN_POINT('',(-10.,-30.2285344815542,2.85416666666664));
#1305=CARTESIAN_POINT('',(-10.,-30.2405626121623,2.8333333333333));
#1306=CARTESIAN_POINT('',(-10.,-30.2646188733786,2.79166666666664));
#1307=CARTESIAN_POINT('',(-10.,-30.2766470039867,2.7708333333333));
#1308=CARTESIAN_POINT('',(-10.,-30.3007032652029,2.72916666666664));
#1309=CARTESIAN_POINT('',(-10.,-30.3127313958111,2.7083333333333));
#1310=CARTESIAN_POINT('',(-10.,-30.3367876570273,2.66666666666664));
#1311=CARTESIAN_POINT('',(-10.,-30.3488157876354,2.6458333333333));
#1312=CARTESIAN_POINT('',(-10.,-30.3728720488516,2.60416666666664));
#1313=CARTESIAN_POINT('',(-10.,-30.3849001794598,2.5833333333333));
#1314=CARTESIAN_POINT('',(-10.,-30.408956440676,2.54166666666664));
#1315=CARTESIAN_POINT('',(-10.,-30.4209845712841,2.5208333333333));
#1316=CARTESIAN_POINT('',(-10.,-30.4450408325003,2.47916666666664));
#1317=CARTESIAN_POINT('',(-10.,-30.4570689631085,2.4583333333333));
#1318=CARTESIAN_POINT('',(-10.,-30.4811252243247,2.41666666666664));
#1319=CARTESIAN_POINT('',(-10.,-30.4931533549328,2.3958333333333));
#1320=CARTESIAN_POINT('',(-10.,-30.5172096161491,2.35416666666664));
#1321=CARTESIAN_POINT('',(-10.,-30.5292377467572,2.3333333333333));
#1322=CARTESIAN_POINT('',(-10.,-30.5532940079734,2.29166666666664));
#1323=CARTESIAN_POINT('',(-10.,-30.5653221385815,2.2708333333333));
#1324=CARTESIAN_POINT('',(-10.,-30.5893783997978,2.22916666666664));
#1325=CARTESIAN_POINT('',(-10.,-30.6014065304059,2.2083333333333));
#1326=CARTESIAN_POINT('',(-10.,-30.6254627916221,2.16666666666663));
#1327=CARTESIAN_POINT('',(-10.,-30.6374909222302,2.1458333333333));
#1328=CARTESIAN_POINT('',(-10.,-30.6615471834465,2.10416666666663));
#1329=CARTESIAN_POINT('',(-10.,-30.6735753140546,2.0833333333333));
#1330=CARTESIAN_POINT('',(-10.,-30.6976315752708,2.04166666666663));
#1331=CARTESIAN_POINT('',(-10.,-30.7096597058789,2.0208333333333));
#1332=CARTESIAN_POINT('',(-10.,-30.7337159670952,1.97916666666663));
#1333=CARTESIAN_POINT('',(-10.,-30.7457440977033,1.9583333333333));
#1334=CARTESIAN_POINT('',(-10.,-30.7698003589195,1.91666666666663));
#1335=CARTESIAN_POINT('',(-10.,-30.7818284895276,1.8958333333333));
#1336=CARTESIAN_POINT('',(-10.,-30.8058847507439,1.85416666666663));
#1337=CARTESIAN_POINT('',(-10.,-30.817912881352,1.8333333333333));
#1338=CARTESIAN_POINT('',(-10.,-30.8419691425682,1.79166666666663));
#1339=CARTESIAN_POINT('',(-10.,-30.8539972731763,1.7708333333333));
#1340=CARTESIAN_POINT('',(-10.,-30.8780535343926,1.72916666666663));
#1341=CARTESIAN_POINT('',(-10.,-30.8900816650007,1.7083333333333));
#1342=CARTESIAN_POINT('',(-10.,-30.9141379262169,1.66666666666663));
#1343=CARTESIAN_POINT('',(-10.,-30.926166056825,1.6458333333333));
#1344=CARTESIAN_POINT('',(-10.,-30.9502223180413,1.60416666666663));
#1345=CARTESIAN_POINT('',(-10.,-30.9622504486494,1.5833333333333));
#1346=CARTESIAN_POINT('',(-10.,-30.9863067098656,1.54166666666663));
#1347=CARTESIAN_POINT('',(-10.,-30.9983348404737,1.5208333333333));
#1348=CARTESIAN_POINT('',(-10.,-31.02239110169,1.47916666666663));
#1349=CARTESIAN_POINT('',(-10.,-31.0344192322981,1.4583333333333));
#1350=CARTESIAN_POINT('',(-10.,-31.0584754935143,1.41666666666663));
#1351=CARTESIAN_POINT('',(-10.,-31.0705036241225,1.3958333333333));
#1352=CARTESIAN_POINT('',(-10.,-31.0945598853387,1.35416666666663));
#1353=CARTESIAN_POINT('',(-10.,-31.1065880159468,1.3333333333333));
#1354=CARTESIAN_POINT('',(-10.,-31.130644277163,1.29166666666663));
#1355=CARTESIAN_POINT('',(-10.,-31.1426724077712,1.2708333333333));
#1356=CARTESIAN_POINT('',(-10.,-31.1547005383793,1.24999999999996));
#1357=B_SPLINE_CURVE_WITH_KNOTS('',3,(#1291,#1292,#1293,#1294,#1295,#1296,#1297,#1298,#1299,
#1300,#1301,#1302,#1303,#1304,#1305,#1306,#1307,#1308,#1309,#1310,#1311,#1312,#1313,#1314,#1315,
#1316,#1317,#1318,#1319,#1320,#1321,#1322,#1323,#1324,#1325,#1326,#1327,#1328,#1329,#1330,#1331,
#1332,#1333,#1334,#1335,#1336,#1337,#1338,#1339,#1340,#1341,#1342,#1343,#1344,#1345,#1346,#1347,
#1348,#1349,#1350,#1351,#1352,#1353,#1354,#1355,#1356),.UNSPECIFIED.,.F.,.F.,(4,2,2,2,2,2,2,2,2,
2,2,2,2,2,2,2,2,2,2,2,2,2,2,2,2,2,2,2,2,2,2,2,4),(0.,0.0721687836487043,0.144337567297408,
0.216506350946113,0.288675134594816,0.360843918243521,0.433012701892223,0.505181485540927,
0.577350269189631,0.649519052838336,0.721687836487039,0.793856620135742,0.866025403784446,
0.93819418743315,1.01036297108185,1.08253175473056,1.15470053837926,1.22686932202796,
1.29903810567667,1.37120688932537,1.44337567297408,1.51554445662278,1.58771324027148,
1.65988202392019,1.73205080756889,1.8042195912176,1.8763883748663,1.948557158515,
2.02072594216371,2.09289472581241,2.16506350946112,2.23723229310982,2.30940107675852),.UNSPECIFIED.);
#1358=EDGE_CURVE('BSEAM565',#1260,#1277,#1357,.T.);
#1359=ORIENTED_EDGE('',*,*,#1261,.F.);
#1360=ORIENTED_EDGE('',*,*,#1278,.F.);
#1361=ORIENTED_EDGE('',*,*,#1358,.T.);
#1362=ORIENTED_EDGE('',*,*,#1358,.F.);
#1363=EDGE_LOOP('',(#1359,#1361,#1360,#1362));
#1364=FACE_BOUND('',#1363,.T.);
#1365=ADVANCED_FACE('F565',(#1364),#1290,.F.);
#1366=CARTESIAN_POINT('',(40.,43.7,0.300000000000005));
#1367=DIRECTION('',(0.577350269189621,0.577350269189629,-0.577350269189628));
#1368=DIRECTION('',(0.,0.707106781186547,0.707106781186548));
#1369=AXIS2_PLACEMENT_3D('',#1366,#1367,#1368);
#1370=PLANE('',#1369);
#1371=ORIENTED_EDGE('',*,*,#945,.F.);
#1372=DIRECTION('',(-0.707106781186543,0.,-0.707106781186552));
#1373=VECTOR('',#1372,1.);
#1374=CARTESIAN_POINT('',(40.,43.7,0.300000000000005));
#1375=LINE('',#1374,#1373);
#1376=EDGE_CURVE('E699',#1164,#215,#1375,.F.);
#1377=ORIENTED_EDGE('',*,*,#1376,.F.);
#1378=DIRECTION('',(0.,-0.707106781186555,-0.70710678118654));
#1379=VECTOR('',#1378,1.);
#1380=CARTESIAN_POINT('',(39.7,43.85,0.149999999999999));
#1381=LINE('',#1380,#1379);
#1382=EDGE_CURVE('E696',#320,#1164,#1381,.T.);
#1383=ORIENTED_EDGE('',*,*,#1382,.F.);
#1384=EDGE_LOOP('',(#1371,#1377,#1383));
#1385=FACE_BOUND('',#1384,.T.);
#1386=ADVANCED_FACE('F561',(#1385),#1370,.T.);
#1387=CARTESIAN_POINT('',(40.,-44.,0.300000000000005));
#1388=DIRECTION('',(0.707106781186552,0.,-0.707106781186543));
#1389=DIRECTION('',(-0.707106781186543,0.,-0.707106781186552));
#1390=AXIS2_PLACEMENT_3D('',#1387,#1388,#1389);
#1391=PLANE('',#1390);
#1392=ORIENTED_EDGE('',*,*,#1376,.T.);
#1393=ORIENTED_EDGE('',*,*,#216,.F.);
#1394=DIRECTION('',(0.707106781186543,0.,0.707106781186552));
#1395=VECTOR('',#1394,1.);
#1396=CARTESIAN_POINT('',(40.,-43.7,0.300000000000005));
#1397=LINE('',#1396,#1395);
#1398=EDGE_CURVE('E691',#1146,#207,#1397,.T.);
#1399=ORIENTED_EDGE('',*,*,#1398,.F.);
#1400=ORIENTED_EDGE('',*,*,#1171,.F.);
#1401=EDGE_LOOP('',(#1392,#1393,#1399,#1400));
#1402=FACE_BOUND('',#1401,.T.);
#1403=ADVANCED_FACE('F557',(#1402),#1391,.T.);
#1404=CARTESIAN_POINT('',(-40.,43.7,0.));
#1405=DIRECTION('',(0.,-0.70710678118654,0.707106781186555));
#1406=DIRECTION('',(0.,-0.707106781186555,-0.70710678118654));
#1407=AXIS2_PLACEMENT_3D('',#1404,#1405,#1406);
#1408=PLANE('',#1407);
#1409=ORIENTED_EDGE('',*,*,#1382,.T.);
#1410=ORIENTED_EDGE('',*,*,#1165,.F.);
#1411=DIRECTION('',(0.,0.707106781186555,0.70710678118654));
#1412=VECTOR('',#1411,1.);
#1413=CARTESIAN_POINT('',(-39.7,43.7,0.));
#1414=LINE('',#1413,#1412);
#1415=EDGE_CURVE('E665',#263,#1156,#1414,.F.);
#1416=ORIENTED_EDGE('',*,*,#1415,.F.);
#1417=ORIENTED_EDGE('',*,*,#327,.F.);
#1418=EDGE_LOOP('',(#1409,#1410,#1416,#1417));
#1419=FACE_BOUND('',#1418,.T.);
#1420=ADVANCED_FACE('F545',(#1419),#1408,.F.);
#1421=CARTESIAN_POINT('',(40.,-43.7,0.300000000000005));
#1422=DIRECTION('',(0.577350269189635,-0.577350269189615,-0.577350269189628));
#1423=DIRECTION('',(-0.707106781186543,0.,-0.707106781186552));
#1424=AXIS2_PLACEMENT_3D('',#1421,#1422,#1423);
#1425=PLANE('',#1424);
#1426=DIRECTION('',(0.,-0.707106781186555,0.70710678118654));
#1427=VECTOR('',#1426,1.);
#1428=CARTESIAN_POINT('',(39.7,-43.85,0.149999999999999));
#1429=LINE('',#1428,#1427);
#1430=EDGE_CURVE('E682',#1146,#1105,#1429,.T.);
#1431=ORIENTED_EDGE('',*,*,#1430,.F.);
#1432=ORIENTED_EDGE('',*,*,#1398,.T.);
#1433=DIRECTION('',(-0.707106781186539,-0.707106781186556,0.));
#1434=VECTOR('',#1433,1.);
#1435=CARTESIAN_POINT('',(40.,-43.7,0.300000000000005));
#1436=LINE('',#1435,#1434);
#1437=EDGE_CURVE('E666',#1105,#207,#1436,.F.);
#1438=ORIENTED_EDGE('',*,*,#1437,.F.);
#1439=EDGE_LOOP('',(#1431,#1432,#1438));
#1440=FACE_BOUND('',#1439,.T.);
#1441=ADVANCED_FACE('F541',(#1440),#1425,.T.);
#1442=CARTESIAN_POINT('',(-39.7,43.7,0.));
#1443=DIRECTION('',(-0.577350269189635,0.577350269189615,-0.577350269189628));
#1444=DIRECTION('',(-0.707106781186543,0.,0.707106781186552));
#1445=AXIS2_PLACEMENT_3D('',#1442,#1443,#1444);
#1446=PLANE('',#1445);
#1447=ORIENTED_EDGE('',*,*,#989,.F.);
#1448=ORIENTED_EDGE('',*,*,#1415,.T.);
#1449=DIRECTION('',(-0.707106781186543,0.,0.707106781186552));
#1450=VECTOR('',#1449,1.);
#1451=CARTESIAN_POINT('',(-39.7,43.7,0.));
#1452=LINE('',#1451,#1450);
#1453=EDGE_CURVE('E685',#39,#1156,#1452,.F.);
#1454=ORIENTED_EDGE('',*,*,#1453,.F.);
#1455=EDGE_LOOP('',(#1447,#1448,#1454));
#1456=FACE_BOUND('',#1455,.T.);
#1457=ADVANCED_FACE('F537',(#1456),#1446,.T.);
#1458=CARTESIAN_POINT('',(40.,-44.,10.2));
#1459=DIRECTION('',(0.707106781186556,0.,0.707106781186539));
#1460=DIRECTION('',(0.707106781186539,0.,-0.707106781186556));
#1461=AXIS2_PLACEMENT_3D('',#1458,#1459,#1460);
#1462=PLANE('',#1461);
#1463=ORIENTED_EDGE('',*,*,#967,.T.);
#1464=ORIENTED_EDGE('',*,*,#1202,.F.);
#1465=DIRECTION('',(-0.707106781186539,0.,0.707106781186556));
#1466=VECTOR('',#1465,1.);
#1467=CARTESIAN_POINT('',(39.85,-43.7,10.35));
#1468=LINE('',#1467,#1466);
#1469=EDGE_CURVE('E670',#199,#1195,#1468,.T.);
#1470=ORIENTED_EDGE('',*,*,#1469,.F.);
#1471=ORIENTED_EDGE('',*,*,#200,.F.);
#1472=EDGE_LOOP('',(#1463,#1464,#1470,#1471));
#1473=FACE_BOUND('',#1472,.T.);
#1474=ADVANCED_FACE('F533',(#1473),#1462,.T.);
#1475=CARTESIAN_POINT('',(40.,-43.7,35.));
#1476=DIRECTION('',(0.707106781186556,-0.707106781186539,0.));
#1477=DIRECTION('',(0.707106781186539,0.707106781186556,0.));
#1478=AXIS2_PLACEMENT_3D('',#1475,#1476,#1477);
#1479=PLANE('',#1478);
#1480=ORIENTED_EDGE('',*,*,#1437,.T.);
#1481=ORIENTED_EDGE('',*,*,#208,.F.);
#1482=DIRECTION('',(0.707106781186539,0.707106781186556,0.));
#1483=VECTOR('',#1482,1.);
#1484=CARTESIAN_POINT('',(39.7,-44.,10.2));
#1485=LINE('',#1484,#1483);
#1486=EDGE_CURVE('E677',#1113,#199,#1485,.T.);
#1487=ORIENTED_EDGE('',*,*,#1486,.F.);
#1488=ORIENTED_EDGE('',*,*,#1114,.F.);
#1489=EDGE_LOOP('',(#1480,#1481,#1487,#1488));
#1490=FACE_BOUND('',#1489,.T.);
#1491=ADVANCED_FACE('F529',(#1490),#1479,.T.);
#1492=CARTESIAN_POINT('',(-40.,-43.7,0.));
#1493=DIRECTION('',(0.,0.70710678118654,0.707106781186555));
#1494=DIRECTION('',(0.,-0.707106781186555,0.70710678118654));
#1495=AXIS2_PLACEMENT_3D('',#1492,#1493,#1494);
#1496=PLANE('',#1495);
#1497=ORIENTED_EDGE('',*,*,#1430,.T.);
#1498=ORIENTED_EDGE('',*,*,#1106,.F.);
#1499=DIRECTION('',(0.,0.707106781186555,-0.70710678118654));
#1500=VECTOR('',#1499,1.);
#1501=CARTESIAN_POINT('',(-39.7,-44.,0.300000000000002));
#1502=LINE('',#1501,#1500);
#1503=EDGE_CURVE('E796',#1148,#1097,#1502,.F.);
#1504=ORIENTED_EDGE('',*,*,#1503,.F.);
#1505=ORIENTED_EDGE('',*,*,#1149,.F.);
#1506=EDGE_LOOP('',(#1497,#1498,#1504,#1505));
#1507=FACE_BOUND('',#1506,.T.);
#1508=ADVANCED_FACE('F525',(#1507),#1496,.F.);
#1509=CARTESIAN_POINT('',(-40.,44.,0.300000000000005));
#1510=DIRECTION('',(-0.707106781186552,0.,-0.707106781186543));
#1511=DIRECTION('',(-0.707106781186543,0.,0.707106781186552));
#1512=AXIS2_PLACEMENT_3D('',#1509,#1510,#1511);
#1513=PLANE('',#1512);
#1514=ORIENTED_EDGE('',*,*,#1453,.T.);
#1515=ORIENTED_EDGE('',*,*,#1157,.F.);
#1516=DIRECTION('',(0.707106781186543,0.,-0.707106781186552));
#1517=VECTOR('',#1516,1.);
#1518=CARTESIAN_POINT('',(-39.85,-43.7,0.150000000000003));
#1519=LINE('',#1518,#1517);
#1520=EDGE_CURVE('E799',#47,#1148,#1519,.T.);
#1521=ORIENTED_EDGE('',*,*,#1520,.F.);
#1522=ORIENTED_EDGE('',*,*,#48,.F.);
#1523=EDGE_LOOP('',(#1514,#1515,#1521,#1522));
#1524=FACE_BOUND('',#1523,.T.);
#1525=ADVANCED_FACE('F518',(#1524),#1513,.T.);
#1526=CARTESIAN_POINT('',(39.7,-44.,10.2));
#1527=DIRECTION('',(0.577350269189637,-0.577350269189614,0.577350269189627));
#1528=DIRECTION('',(0.707106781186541,0.,-0.707106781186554));
#1529=AXIS2_PLACEMENT_3D('',#1526,#1527,#1528);
#1530=PLANE('',#1529);
#1531=ORIENTED_EDGE('',*,*,#1486,.T.);
#1532=ORIENTED_EDGE('',*,*,#1469,.T.);
#1533=DIRECTION('',(0.,0.707106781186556,0.707106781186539));
#1534=VECTOR('',#1533,1.);
#1535=CARTESIAN_POINT('',(39.7,-44.,10.2));
#1536=LINE('',#1535,#1534);
#1537=EDGE_CURVE('E802',#1113,#1195,#1536,.T.);
#1538=ORIENTED_EDGE('',*,*,#1537,.F.);
#1539=EDGE_LOOP('',(#1531,#1532,#1538));
#1540=FACE_BOUND('',#1539,.T.);
#1541=ADVANCED_FACE('F514',(#1540),#1530,.T.);
#1542=CARTESIAN_POINT('',(-39.7,-44.,0.300000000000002));
#1543=DIRECTION('',(-0.577350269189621,-0.577350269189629,-0.577350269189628));
#1544=DIRECTION('',(0.,0.707106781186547,-0.707106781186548));
#1545=AXIS2_PLACEMENT_3D('',#1542,#1543,#1544);
#1546=PLANE('',#1545);
#1547=ORIENTED_EDGE('',*,*,#1520,.T.);
#1548=ORIENTED_EDGE('',*,*,#1503,.T.);
#1549=DIRECTION('',(-0.707106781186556,0.707106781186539,0.));
#1550=VECTOR('',#1549,1.);
#1551=CARTESIAN_POINT('',(-39.7,-44.,0.300000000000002));
#1552=LINE('',#1551,#1550);
#1553=EDGE_CURVE('E805',#47,#1097,#1552,.F.);
#1554=ORIENTED_EDGE('',*,*,#1553,.F.);
#1555=EDGE_LOOP('',(#1547,#1548,#1554));
#1556=FACE_BOUND('',#1555,.T.);
#1557=ADVANCED_FACE('F510',(#1556),#1546,.T.);
#1558=CARTESIAN_POINT('',(-105.,-43.7,10.5));
#1559=DIRECTION('',(0.,0.707106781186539,-0.707106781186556));
#1560=DIRECTION('',(0.,0.707106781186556,0.707106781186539));
#1561=AXIS2_PLACEMENT_3D('',#1558,#1559,#1560);
#1562=PLANE('',#1561);
#1563=ORIENTED_EDGE('',*,*,#1537,.T.);
#1564=ORIENTED_EDGE('',*,*,#1196,.F.);
#1565=DIRECTION('',(0.,-0.707106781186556,-0.707106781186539));
#1566=VECTOR('',#1565,1.);
#1567=CARTESIAN_POINT('',(-39.7,-43.7,10.5));
#1568=LINE('',#1567,#1566);
#1569=EDGE_CURVE('E807',#1095,#1187,#1568,.F.);
#1570=ORIENTED_EDGE('',*,*,#1569,.F.);
#1571=ORIENTED_EDGE('',*,*,#1120,.F.);
#1572=EDGE_LOOP('',(#1563,#1564,#1570,#1571));
#1573=FACE_BOUND('',#1572,.T.);
#1574=ADVANCED_FACE('F506',(#1573),#1562,.F.);
#1575=CARTESIAN_POINT('',(-39.7,-44.,35.));
#1576=DIRECTION('',(-0.707106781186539,-0.707106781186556,0.));
#1577=DIRECTION('',(0.707106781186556,-0.707106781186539,0.));
#1578=AXIS2_PLACEMENT_3D('',#1575,#1576,#1577);
#1579=PLANE('',#1578);
#1580=ORIENTED_EDGE('',*,*,#1553,.T.);
#1581=ORIENTED_EDGE('',*,*,#1098,.F.);
#1582=DIRECTION('',(0.707106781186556,-0.707106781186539,0.));
#1583=VECTOR('',#1582,1.);
#1584=CARTESIAN_POINT('',(-39.85,-43.85,10.2));
#1585=LINE('',#1584,#1583);
#1586=EDGE_CURVE('E809',#55,#1095,#1585,.T.);
#1587=ORIENTED_EDGE('',*,*,#1586,.F.);
#1588=ORIENTED_EDGE('',*,*,#56,.F.);
#1589=EDGE_LOOP('',(#1580,#1581,#1587,#1588));
#1590=FACE_BOUND('',#1589,.T.);
#1591=ADVANCED_FACE('F502',(#1590),#1579,.T.);
#1592=CARTESIAN_POINT('',(-39.7,-43.7,10.5));
#1593=DIRECTION('',(-0.577350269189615,-0.577350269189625,0.577350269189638));
#1594=DIRECTION('',(0.,-0.707106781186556,-0.707106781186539));
#1595=AXIS2_PLACEMENT_3D('',#1592,#1593,#1594);
#1596=PLANE('',#1595);
#1597=ORIENTED_EDGE('',*,*,#1586,.T.);
#1598=ORIENTED_EDGE('',*,*,#1569,.T.);
#1599=DIRECTION('',(-0.707106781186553,0.,-0.707106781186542));
#1600=VECTOR('',#1599,1.);
#1601=CARTESIAN_POINT('',(-39.7,-43.7,10.5));
#1602=LINE('',#1601,#1600);
#1603=EDGE_CURVE('E488',#55,#1187,#1602,.F.);
#1604=ORIENTED_EDGE('',*,*,#1603,.F.);
#1605=EDGE_LOOP('',(#1597,#1598,#1604));
#1606=FACE_BOUND('',#1605,.T.);
#1607=ADVANCED_FACE('F499',(#1606),#1596,.T.);
#1608=CARTESIAN_POINT('',(-39.7,-30.,10.5));
#1609=DIRECTION('',(-0.707106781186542,0.,0.707106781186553));
#1610=DIRECTION('',(0.707106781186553,0.,0.707106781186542));
#1611=AXIS2_PLACEMENT_3D('',#1608,#1609,#1610);
#1612=PLANE('',#1611);
#1613=ORIENTED_EDGE('',*,*,#1603,.T.);
#1614=ORIENTED_EDGE('',*,*,#1188,.F.);
#1615=ORIENTED_EDGE('',*,*,#1014,.F.);
#1616=ORIENTED_EDGE('',*,*,#64,.F.);
#1617=EDGE_LOOP('',(#1613,#1614,#1615,#1616));
#1618=FACE_BOUND('',#1617,.T.);
#1619=ADVANCED_FACE('F490',(#1618),#1612,.T.);
#1620=CARTESIAN_POINT('',(-40.,63.9994038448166,16.5));
#1621=DIRECTION('',(0.,0.,1.));
#1622=DIRECTION('',(0.,-1.,0.));
#1623=AXIS2_PLACEMENT_3D('',#1620,#1621,#1622);
#1624=PLANE('',#1623);
#1625=ORIENTED_EDGE('',*,*,#345,.T.);
#1626=ORIENTED_EDGE('',*,*,#622,.T.);
#1627=ORIENTED_EDGE('',*,*,#1080,.F.);
#1628=ORIENTED_EDGE('',*,*,#274,.F.);
#1629=ORIENTED_EDGE('',*,*,#982,.F.);
#1630=ORIENTED_EDGE('',*,*,#32,.T.);
#1631=ORIENTED_EDGE('',*,*,#916,.F.);
#1632=EDGE_LOOP('',(#1625,#1626,#1627,#1628,#1629,#1630,#1631));
#1633=FACE_BOUND('',#1632,.T.);
#1634=ADVANCED_FACE('F274',(#1633),#1624,.T.);
#1635=ORIENTED_EDGE('',*,*,#313,.F.);
#1636=ORIENTED_EDGE('',*,*,#872,.F.);
#1637=ORIENTED_EDGE('',*,*,#677,.T.);
#1638=ORIENTED_EDGE('',*,*,#661,.F.);
#1639=ORIENTED_EDGE('',*,*,#732,.T.);
#1640=ORIENTED_EDGE('',*,*,#718,.F.);
#1641=ORIENTED_EDGE('',*,*,#739,.T.);
#1642=ORIENTED_EDGE('',*,*,#650,.F.);
#1643=ORIENTED_EDGE('',*,*,#692,.T.);
#1644=ORIENTED_EDGE('',*,*,#879,.F.);
#1645=ORIENTED_EDGE('',*,*,#300,.F.);
#1646=ORIENTED_EDGE('',*,*,#894,.F.);
#1647=ORIENTED_EDGE('',*,*,#794,.T.);
#1648=ORIENTED_EDGE('',*,*,#778,.F.);
#1649=ORIENTED_EDGE('',*,*,#849,.T.);
#1650=ORIENTED_EDGE('',*,*,#835,.F.);
#1651=ORIENTED_EDGE('',*,*,#856,.T.);
#1652=ORIENTED_EDGE('',*,*,#767,.F.);
#1653=ORIENTED_EDGE('',*,*,#809,.T.);
#1654=ORIENTED_EDGE('',*,*,#901,.F.);
#1655=ORIENTED_EDGE('',*,*,#287,.F.);
#1656=ORIENTED_EDGE('',*,*,#1073,.F.);
#1657=ORIENTED_EDGE('',*,*,#607,.T.);
#1658=ORIENTED_EDGE('',*,*,#375,.T.);
#1659=ORIENTED_EDGE('',*,*,#1058,.F.);
#1660=ORIENTED_EDGE('',*,*,#228,.F.);
#1661=ORIENTED_EDGE('',*,*,#938,.F.);
#1662=EDGE_LOOP('',(#1635,#1636,#1637,#1638,#1639,#1640,#1641,#1642,#1643,#1644,#1645,#1646,
#1647,#1648,#1649,#1650,#1651,#1652,#1653,#1654,#1655,#1656,#1657,#1658,#1659,#1660,#1661));
#1663=FACE_BOUND('',#1662,.T.);
#1664=ADVANCED_FACE('F767',(#1663),#1624,.T.);
#1665=ORIENTED_EDGE('',*,*,#102,.T.);
#1666=ORIENTED_EDGE('',*,*,#552,.F.);
#1667=ORIENTED_EDGE('',*,*,#575,.T.);
#1668=ORIENTED_EDGE('',*,*,#1036,.F.);
#1669=ORIENTED_EDGE('',*,*,#241,.F.);
#1670=ORIENTED_EDGE('',*,*,#1051,.F.);
#1671=ORIENTED_EDGE('',*,*,#362,.T.);
#1672=ORIENTED_EDGE('',*,*,#923,.F.);
#1673=ORIENTED_EDGE('',*,*,#77,.T.);
#1674=ORIENTED_EDGE('',*,*,#1004,.F.);
#1675=EDGE_LOOP('',(#1665,#1666,#1667,#1668,#1669,#1670,#1671,#1672,#1673,#1674));
#1676=FACE_BOUND('',#1675,.T.);
#1677=ADVANCED_FACE('F1183',(#1676),#1624,.T.);
#1678=ORIENTED_EDGE('',*,*,#184,.F.);
#1679=ORIENTED_EDGE('',*,*,#1029,.F.);
#1680=ORIENTED_EDGE('',*,*,#584,.T.);
#1681=ORIENTED_EDGE('',*,*,#541,.F.);
#1682=ORIENTED_EDGE('',*,*,#152,.F.);
#1683=ORIENTED_EDGE('',*,*,#960,.F.);
#1684=EDGE_LOOP('',(#1678,#1679,#1680,#1681,#1682,#1683));
#1685=FACE_BOUND('',#1684,.T.);
#1686=ADVANCED_FACE('F1174',(#1685),#1624,.T.);
#1687=CLOSED_SHELL('',(#88,#130,#170,#252,#331,#528,#563,#595,#627,#665,#697,#722,#744,#782,
#814,#839,#861,#883,#905,#927,#949,#971,#993,#1018,#1040,#1062,#1084,#1135,#1175,#1208,#1228,
#1248,#1265,#1285,#1365,#1386,#1403,#1420,#1441,#1457,#1474,#1491,#1508,#1525,#1541,#1557,#1574,
#1591,#1607,#1619,#1634,#1664,#1677,#1686));
#1688=MANIFOLD_SOLID_BREP('B2',#1687);
#1689=ADVANCED_BREP_SHAPE_REPRESENTATION('',(#18,#1688),#14);
#1690=SHAPE_DEFINITION_REPRESENTATION(#9,#1689);
ENDSEC;
END-ISO-10303-21;
